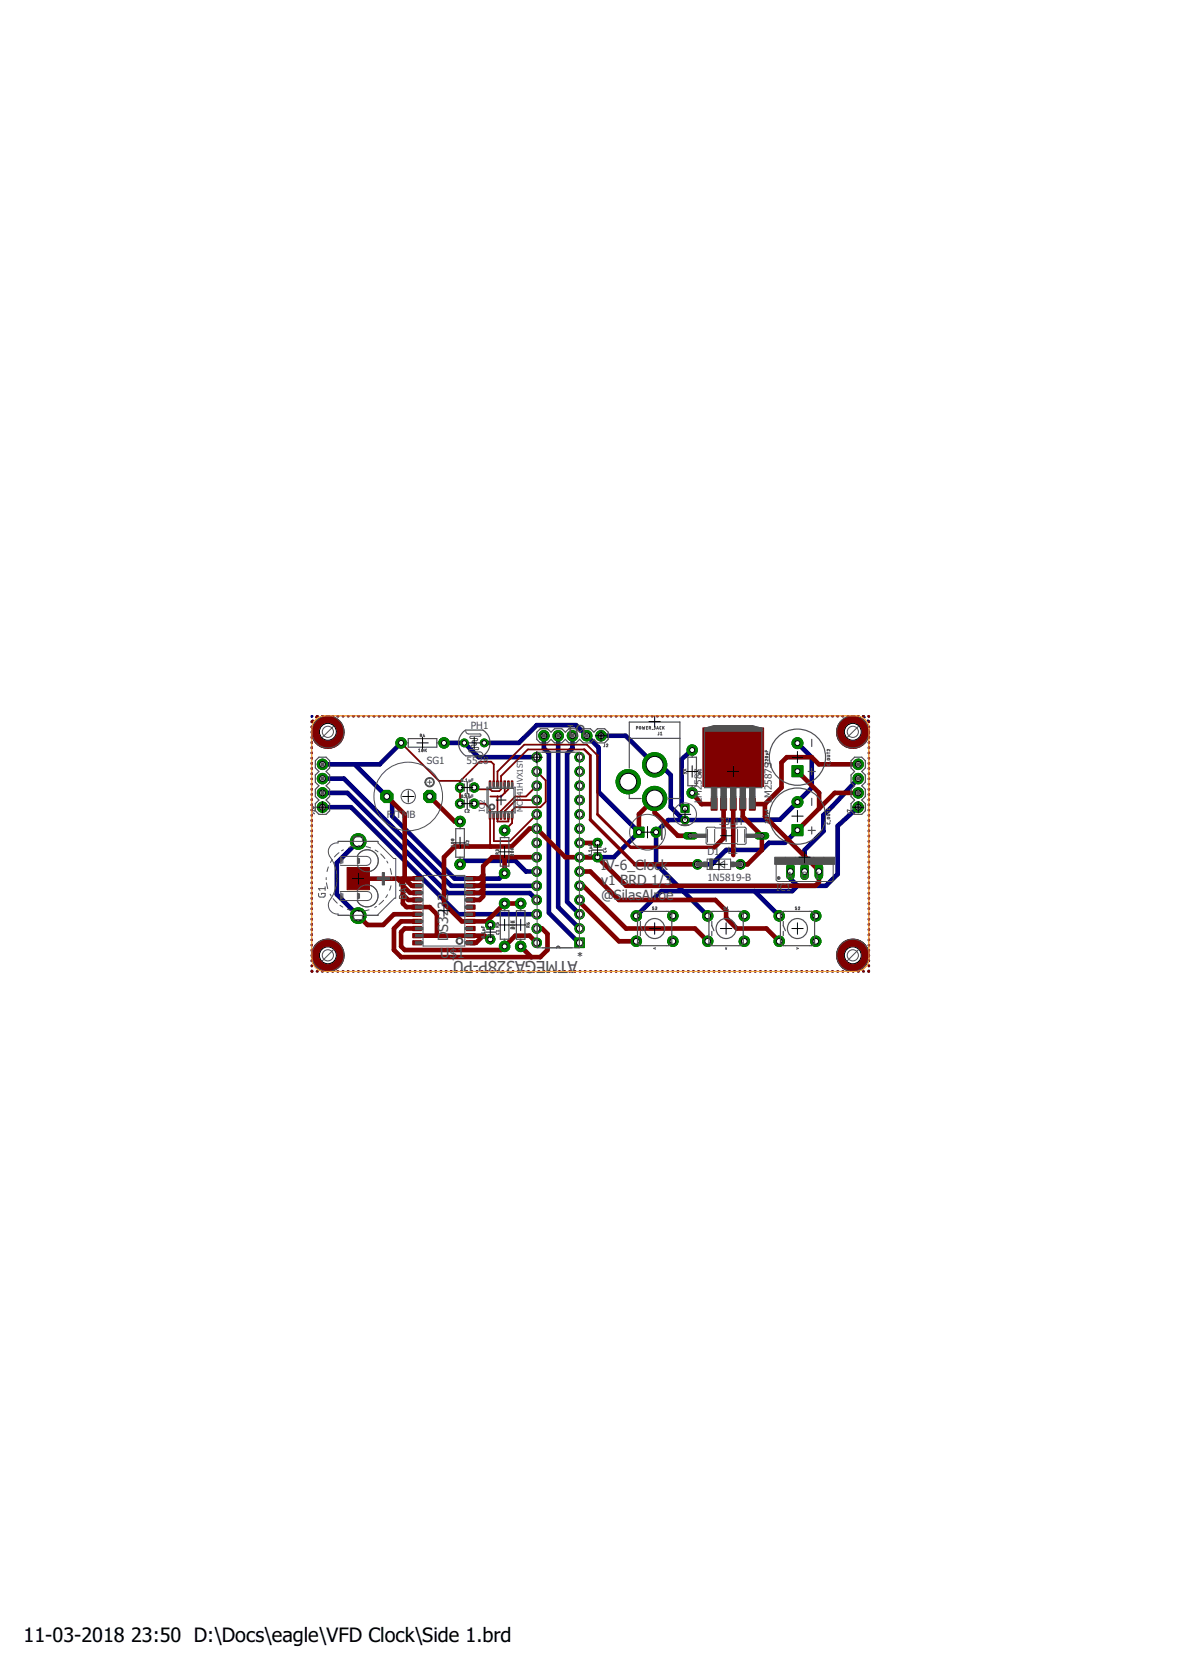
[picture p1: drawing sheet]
<svg xmlns="http://www.w3.org/2000/svg" width="210mm" height="297mm" viewBox="0 0 210 297" stroke-linecap="round" stroke-linejoin="round" font-family="sans-serif">
<defs><g id="words">
<g font-size="3.5">
<text x="4.2" y="291.8">11-03-2018</text>
<text x="23.3" y="291.8">23:50 D:\Docs\eagle\VFD Clock\Side 1.brd</text>
</g>
<g font-size="2.9" fill="#505050">
<text x="104.1" y="128.8" transform="rotate(-180 104.1 128.8)">U1</text>
<text x="102.7" y="170.8" transform="rotate(-180 102.7 170.8)">ATMEGA328P-PU</text>
</g>
<g font-size="2.5" fill="#505050">
<text x="106.8" y="154.7">IV-6_Clock</text>
<text x="79.7" y="161.5" transform="rotate(-90 79.7 161.5)">32</text>
<text x="106.8" y="157.3">v1 BRD 1/3</text>
<text x="106.8" y="160">@SilasAlroe</text>
<text x="79.7" y="167.3" transform="rotate(-90 79.7 167.3)">D</text>
<text x="79.7" y="165.7" transform="rotate(-90 79.7 165.7)">S32</text>
<text x="78.2" y="170.3">U$1</text>
</g>
<g font-size="1.8" fill="#505050">
<text x="83.7" y="129.5">PH1</text>
<text x="75.9" y="135.9">SG1</text>
<text x="82.9" y="135.9">5528</text>
<text x="124.7" y="142.7" transform="rotate(-90 124.7 142.7)">LM2587</text>
<text x="137.2" y="142.7" transform="rotate(-90 137.2 142.7)">LM2587S</text>
<text x="68.7" y="145.4">F/TMB</text>
<text x="127.8" y="146.6">3</text>
<text x="128.8" y="146.6">3µ</text>
<text x="130.8" y="146.6">H</text>
<text x="125.7" y="152">D1</text>
<text x="129.3" y="151.7">L1</text>
<text x="125.7" y="156.6">1N5819-B</text>
<text x="137.9" y="158.4">IC1</text>
<text x="139.8" y="156.2">A</text>
<text x="142.4" y="156.2">O</text>
<text x="144.9" y="156.2">I</text>
<text x="103.6" y="168.7" transform="rotate(-180 103.6 168.7)">*</text>
</g>
<g font-size="1.4" fill="#505050">
<text x="92.9" y="143.2" transform="rotate(-90 92.9 143.2)">CP41HVX1ST</text>
<text x="86.2" y="144.3" transform="rotate(-90 86.2 144.3)">IC2</text>
<text x="92.9" y="144.3" transform="rotate(-90 92.9 144.3)">M</text>
</g>
</g></defs>
<g fill="#000080" stroke="#000080" stroke-width=".18">
<path d="M56 168a2.88 2.88 0 0 1 4.6 .2 2.88 2.88 0 0 1-1.5 4.4 2.88 2.88 0 0 1-3.7-2.8h2.5a.35 .35 0 0 1 .5-.4 .35 .35 0 0 1 .1 .6 .35 .35 0 0 1-.6-.1l-2.5-.1 .1-.6z" fill-rule="evenodd"/>
<path d="M56 128.4a2.89 2.89 0 0 1 4.7 .1 2.89 2.89 0 0 1-1.5 4.4 2.89 2.89 0 0 1-3.8-2.7h2.5a.35 .35 0 0 1 .5-.4 .35 .35 0 0 1 .1 .6 .35 .35 0 0 1-.6-.2h-2.5l.1-.7z" fill-rule="evenodd"/>
<path d="M149.3 128.4a2.88 2.88 0 0 1 4.7 .1 2.88 2.88 0 0 1-1.6 4.4 2.88 2.88 0 0 1-3.7-2.7h2.5a.35 .35 0 0 1 .6-.3 .35 .35 0 0 1 0 .6 .35 .35 0 0 1-.6-.3h-2.5l.3-1.3z" fill-rule="evenodd"/>
<path d="M149.8 167.6a2.89 2.89 0 0 1 4.4 .9 2.89 2.89 0 0 1-2 4.1 2.89 2.89 0 0 1-3.5-2.8h2.5a.35 .35 0 0 1 .6-.2 .35 .35 0 0 1 0 .6 .35 .35 0 0 1-.6-.3l-2.5-.1a2.87 2.87 0 0 1 1.1-2.2z" fill-rule="evenodd"/>
</g>
<g fill="none" stroke="#000080" stroke-width=".83">
<path d="M57.3 138.4h3.8l19.1 19.1h15.2M63 135.9l6.7 6.6v2.6l11.1 11.1h7.9l1-1M71.3 132.1l-3.8 3.8h-10.2M78.9 132.1h3.6l2.5 2.5h10.4M86.1 132.1h6.1l3.2-3.2h7l4 4v7.9l7.2 7.1-4.5 4.5h-6.1M96.7 130.8v2.2l.9 .9v28.4l5.4 5.3M99.2 130.8v30.4l3.8 3.9M101.7 130.8v2.2l-.9 1v26.3l2.2 2.2M106.8 130.8h4.4l5.2 5.2h1l1.8 1.8v5.7l2.3 2.3M123 133.3l-1.9 1.7v8.1l.7 .6M141.7 132.1l2.6 2.5v5.4l-5.7 5.7-19.8 .1-2.2 2.1v5.7l9.2 9.2M152.5 138.4l-6.2 6.5v2.9l-3.3 3.3v3.8"/>
<path d="M57.3 140.9h4.5l17.8 17.8h14.6l1.2 1.3M57.3 143.5h5.1l19 19h14M63.7 149.6l-3.8 3.8v5.6l3.8 3.8M81.8 153.6l.6-.6h9.2l1.9 1.9h1.9M134.1 158.4l4.4 4.4M140.5 154.9v1.3l1.2 1.3M141.7 142.2v.4M141.7 157.5l-.9 .9h-23.3l-4.4 4.4M141.7 147.6l-2.2 2.2h-2.8l-1.3 1.3h-6.3l-2.6 2.5h-2.5M152.5 143.5l-3.6 3.3v8.6l-2.1 2.1h-5.1"/>
</g>
<g fill="none" stroke="#000080" stroke-width=".42">
<path d="M55.4 128.2v.1M55.4 129.2v.1M55.4 130.1v.1M55.4 131v.1M55.4 131.9v.1M55.4 132.8v.2M55.4 133.8v.1M55.4 134.7v.1M55.4 135.6v.1M55.4 136.5v.2M55.4 137.5v.1M55.4 138.4v.1"/>
<path d="M55.4 139.3v.1M55.5 127.3l-.1 .1M56.3 127.3h.1M57.3 127.3h.1M58.2 127.3h.1M59.1 127.3h.1M60 127.3h.1M60.9 127.3h.1M61.8 127.3h.1M62.7 127.3h.1M63.6 127.3h.2M64.6 127.3h.1"/>
<path d="M65.5 127.3h.1M66.4 127.3h.1M67.3 127.3h.1M68.2 127.3h.1M69.2 127.3h.1M70.1 127.3h.1M71 127.3h.1M71.9 127.3h.1M72.8 127.3h.1M73.7 127.3h.1M74.6 127.3h.1M75.6 127.3h.1"/>
<path d="M76.5 127.3h.1M77.4 127.3h.1M78.3 127.3h.1M79.2 127.3h.1M80.1 127.3h.1M81 127.3h.2M82 127.3h.1M82.9 127.3h.1M83.8 127.3h.1M84.7 127.3h.1M85.6 127.3h.1M86.6 127.3h.1"/>
<path d="M87.5 127.3h.1M88.4 127.3h.1M89.3 127.3h.1M90.2 127.3h.1M91.1 127.3h.1M92 127.3h.1M93 127.3h.1M93.9 127.3h.1M94.8 127.3h.1M95.7 127.3h.1M96.6 127.3h.1M97.5 127.3h.1"/>
<path d="M98.4 127.3h.2M99.4 127.3h.1M100.3 127.3h.1M101.2 127.3h.1M102.1 127.3h.1M103 127.3h.1M103.9 127.3h.1M104.9 127.3h.1M105.8 127.3h.1M106.7 127.3h.1M107.6 127.3h.1M108.5 127.3h.1"/>
<path d="M109.4 127.3h.1M110.3 127.3h.1M111.3 127.3h.1M112.2 127.3h.1M113.1 127.3h.1M114 127.3h.1M114.9 127.3h.1M115.8 127.3h.2M116.8 127.3h.1M117.7 127.3h.1M118.6 127.3h.1M119.5 127.3h.1"/>
<path d="M120.4 127.3h.1M121.3 127.3h.1M122.3 127.3h.1M123.2 127.3h.1M124.1 127.3h.1M125 127.3h.1M125.9 127.3h.1M126.8 127.3h.1M127.7 127.3h.1M128.7 127.3h.1M129.6 127.3h.1M130.5 127.3h.1"/>
<path d="M131.4 127.3h.1M132.3 127.3h.1M133.2 127.3h.1M134.2 127.3h.1M135.1 127.3h.1M136 127.3h.1M136.9 127.3h.1M137.8 127.3h.1M138.7 127.3h.1M139.7 127.3h.1M140.6 127.3h.1M141.5 127.3h.1"/>
<path d="M142.4 127.3h.1M143.3 127.3h.1M144.2 127.3h.1M145.1 127.3h.1M146 127.3h.2M147 127.3h.1M147.9 127.3h.1M148.8 127.3h.1M149.7 127.3h.1M150.6 127.3h.1M151.6 127.3h.1M152.5 127.3h.1"/>
<path d="M153.4 127.3l.3 .2M154.2 128.1l.2 .3M154.4 129.2v.1M154.4 130.1v.1M154.4 131v.1M154.4 132v.1M154.4 132.9v.1M154.4 133.8v.1M154.4 134.7v.1M154.4 135.6v.2M154.4 136.6v.1M154.4 137.5v.1"/>
<path d="M154.4 138.4v.1M154.4 139.3v.1M55.4 140.2v.2M55.4 141.2v.1M55.4 142.1v.1M55.4 143v.1M55.4 143.9v.1M55.4 144.9v.1M55.4 145.8v.1M55.4 146.7v.1M55.4 147.6v.1M55.4 148.5v.2"/>
<path d="M55.4 149.5v.1M55.4 150.4v.1M55.4 151.3v.1M55.4 152.3v.1M55.4 153.2v.1M55.4 154.1v.1M55.4 155v.1M55.4 155.9v.2M55.4 156.9v.1M55.4 157.8v.1M55.4 158.7v.1M55.4 159.6v.1"/>
<path d="M154.4 140.3v.1M154.4 141.2v.1M154.4 142.1v.1M154.4 143v.2M154.4 144v.1M154.4 144.9v.1M154.4 145.8v.1M154.4 146.7v.1M154.4 147.6v.2M154.4 148.6v.1M154.4 149.5v.1M154.4 150.4v.1"/>
<path d="M154.4 151.3v.1M154.4 152.3v.1M154.4 153.2v.1M154.4 154.1v.1M154.4 155v.1M154.4 156v.1M154.4 156.9v.1M154.4 157.8v.1M154.4 158.7v.1M154.4 159.6v.1M55.4 160.5v.2M55.4 161.5v.1"/>
<path d="M55.4 162.4v.1M55.4 163.3v.1M55.4 164.3v.1M55.4 165.2v.1M55.4 166.1v.1M55.4 167v.1M55.4 168v.1M55.4 168.9v.1M55.4 169.8v.1M55.4 170.7v.1M55.4 171.6v.1M55.4 172.6l.1 .1"/>
<path d="M56.3 172.7h.1M57.3 172.7h.1M58.2 172.7h.1M59.1 172.7h.1M60 172.7h.1M60.9 172.7h.1M61.8 172.7h.1M62.7 172.7h.1M63.6 172.7h.2M64.6 172.7h.1M65.5 172.7h.1M66.4 172.7h.1"/>
<path d="M67.3 172.7h.1M68.2 172.7h.1M69.2 172.7h.1M70.1 172.7h.1M71 172.7h.1M71.9 172.7h.1M72.8 172.7h.1M73.7 172.7h.1M74.7 172.7h.1M75.6 172.7h.1M76.5 172.7h.1M77.4 172.7h.1"/>
<path d="M78.3 172.7h.1M79.2 172.7h.1M80.1 172.7h.1M81.1 172.7h.1M82 172.7h.1M82.9 172.7h.1M83.8 172.7h.1M84.7 172.7h.1M85.6 172.7h.1M86.6 172.7h.1M87.5 172.7h.1M88.4 172.7h.1"/>
<path d="M89.3 172.7h.1M90.2 172.7h.1M91.1 172.7h.1M92.1 172.7h.1M93 172.7h.1M93.9 172.7h.1M94.8 172.7h.1M95.7 172.7h.1M96.6 172.7h.1M97.6 172.7h.1M98.5 172.7h.1M99.4 172.7h.1"/>
<path d="M100.3 172.7h.1M101.2 172.7h.1M102.1 172.7h.1M103 172.7h.1M103.9 172.7h.2M104.9 172.7h.1M105.8 172.7h.1M106.7 172.7h.1M107.6 172.7h.1M108.5 172.7h.1M109.5 172.7h.1M110.4 172.7h.1"/>
<path d="M111.3 172.7h.1M112.2 172.7h.1M113.1 172.7h.1M114 172.7h.1M115 172.7h.1M115.9 172.7h.1M116.8 172.7h.1M117.7 172.7h.1M118.6 172.7h.1M119.5 172.7h.1M120.4 172.7h.1M121.4 172.7h.1"/>
<path d="M122.3 172.7h.1M123.2 172.7h.1M124.1 172.7h.1M125 172.7h.1M125.9 172.7h.1M126.9 172.7h.1M127.8 172.7h.1M128.7 172.7h.1M129.6 172.7h.1M130.5 172.7h.1M131.4 172.7h.1M132.4 172.7h.1"/>
<path d="M133.3 172.7h.1M134.2 172.7h.1M135.1 172.7h.1M136 172.7h.1M136.9 172.7h.1M137.8 172.7h.1M138.8 172.7h.1M139.7 172.7h.1M140.6 172.7h.1M141.5 172.7h.1M142.4 172.7h.1M143.3 172.7h.1"/>
<path d="M144.3 172.7h.1M145.2 172.7h.1M146.1 172.7h.1M147 172.7h.1M147.9 172.7h.1M148.8 172.7h.1M149.8 172.7h.1M150.7 172.7h.1M151.6 172.7h.1M152.5 172.7h.1M153.4 172.7h.1M154.4 160.6v.1"/>
<path d="M154.4 161.5v.1M154.4 162.4v.1M154.4 163.3v.1M154.4 164.3v.1M154.4 165.2v.1M154.4 166.1v.1M154.4 167v.1M154.4 168v.1M154.4 168.9v.1M154.4 169.8v.1M154.4 170.7v.1M154.4 171.6v.1"/>
<path d="M154.4 172.6l-.1 .1"/>
</g>
<circle cx="121.8" cy="145.8" r=".7" fill="#008000" stroke="#008000" stroke-width=".18"/>
<circle cx="121.8" cy="145.8" r=".44" fill="#fff" stroke="#000" stroke-width=".18"/>
<path d="M121.1 143h1.3v1.4h-1.3z" fill="#008000" stroke="#008000" stroke-width=".18"/>
<circle cx="121.8" cy="143.7" r=".44" fill="#fff" stroke="#000" stroke-width=".18"/>
<path d="M112.7 147h1.7v1.8h-1.7z" fill="#008000" stroke="#008000" stroke-width=".18"/>
<circle cx="113.6" cy="147.9" r=".44" fill="#fff" stroke="#000" stroke-width=".18"/>
<circle cx="116.6" cy="147.9" r=".89" fill="#008000" stroke="#008000" stroke-width=".18"/>
<circle cx="116.6" cy="147.9" r=".44" fill="#fff" stroke="#000" stroke-width=".18"/>
<circle cx="141.7" cy="142.6" r=".97" fill="#008000" stroke="#008000" stroke-width=".18"/>
<circle cx="141.7" cy="142.6" r=".44" fill="#fff" stroke="#000" stroke-width=".18"/>
<path d="M140.8 146.6h1.9v1.9h-1.9z" fill="#008000" stroke="#008000" stroke-width=".18"/>
<circle cx="141.7" cy="147.6" r=".44" fill="#fff" stroke="#000" stroke-width=".18"/>
<circle cx="141.7" cy="132.1" r=".97" fill="#008000" stroke="#008000" stroke-width=".18"/>
<circle cx="141.7" cy="132.1" r=".44" fill="#fff" stroke="#000" stroke-width=".18"/>
<path d="M140.8 136.1h1.9v2h-1.9z" fill="#008000" stroke="#008000" stroke-width=".18"/>
<circle cx="141.7" cy="137.1" r=".44" fill="#fff" stroke="#000" stroke-width=".18"/>
<circle cx="124" cy="153.6" r=".85" fill="#008000" stroke="#008000" stroke-width=".18"/>
<circle cx="124" cy="153.6" r=".55" fill="#fff" stroke="#000" stroke-width=".18"/>
<circle cx="131.6" cy="153.6" r=".85" fill="#008000" stroke="#008000" stroke-width=".18"/>
<circle cx="131.6" cy="153.6" r=".55" fill="#fff" stroke="#000" stroke-width=".18"/>
<path d="M134.7 148.6h1.4" fill="none" stroke="#008000" stroke-width="1.3"/>
<circle cx="135.4" cy="148.6" r=".4" fill="#fff" stroke="#000" stroke-width=".18"/>
<path d="M122 148.6h1.4" fill="none" stroke="#008000" stroke-width="1.3"/>
<circle cx="122.7" cy="148.6" r=".4" fill="#fff" stroke="#000" stroke-width=".18"/>
<circle cx="123" cy="133.3" r=".93" fill="#008000" stroke="#008000" stroke-width=".18"/>
<circle cx="123" cy="133.3" r=".44" fill="#fff" stroke="#000" stroke-width=".18"/>
<circle cx="123" cy="140.9" r=".93" fill="#008000" stroke="#008000" stroke-width=".18"/>
<circle cx="123" cy="140.9" r=".44" fill="#fff" stroke="#000" stroke-width=".18"/>
<circle cx="116.4" cy="141.9" r="2.16" fill="#008000" stroke="#008000" stroke-width=".18"/>
<circle cx="116.4" cy="141.9" r="1.5" fill="#fff" stroke="#000" stroke-width=".18"/>
<circle cx="116.4" cy="136" r="2.16" fill="#008000" stroke="#008000" stroke-width=".18"/>
<circle cx="116.4" cy="136" r="1.5" fill="#fff" stroke="#000" stroke-width=".18"/>
<circle cx="111.7" cy="139" r="2.16" fill="#008000" stroke="#008000" stroke-width=".18"/>
<circle cx="111.7" cy="139" r="1.5" fill="#fff" stroke="#000" stroke-width=".18"/>
<circle cx="152.5" cy="143.5" r=".93" fill="#008000" stroke="#008000" stroke-width=".18"/>
<circle cx="152.5" cy="143.5" r=".51" fill="#fff" stroke="#000" stroke-width=".18"/>
<circle cx="152.5" cy="140.9" r=".93" fill="#008000" stroke="#008000" stroke-width=".18"/>
<circle cx="152.5" cy="140.9" r=".51" fill="#fff" stroke="#000" stroke-width=".18"/>
<circle cx="152.5" cy="138.4" r=".93" fill="#008000" stroke="#008000" stroke-width=".18"/>
<circle cx="152.5" cy="138.4" r=".51" fill="#fff" stroke="#000" stroke-width=".18"/>
<circle cx="152.5" cy="135.9" r=".93" fill="#008000" stroke="#008000" stroke-width=".18"/>
<circle cx="152.5" cy="135.9" r=".51" fill="#fff" stroke="#000" stroke-width=".18"/>
<circle cx="57.3" cy="143.5" r=".93" fill="#008000" stroke="#008000" stroke-width=".18"/>
<circle cx="57.3" cy="143.5" r=".51" fill="#fff" stroke="#000" stroke-width=".18"/>
<circle cx="57.3" cy="140.9" r=".93" fill="#008000" stroke="#008000" stroke-width=".18"/>
<circle cx="57.3" cy="140.9" r=".51" fill="#fff" stroke="#000" stroke-width=".18"/>
<circle cx="57.3" cy="138.4" r=".93" fill="#008000" stroke="#008000" stroke-width=".18"/>
<circle cx="57.3" cy="138.4" r=".51" fill="#fff" stroke="#000" stroke-width=".18"/>
<circle cx="57.3" cy="135.9" r=".93" fill="#008000" stroke="#008000" stroke-width=".18"/>
<circle cx="57.3" cy="135.9" r=".51" fill="#fff" stroke="#000" stroke-width=".18"/>
<circle cx="86.1" cy="132.1" r=".7" fill="#008000" stroke="#008000" stroke-width=".18"/>
<circle cx="86.1" cy="132.1" r=".4" fill="#fff" stroke="#000" stroke-width=".18"/>
<circle cx="82.5" cy="132.1" r=".7" fill="#008000" stroke="#008000" stroke-width=".18"/>
<circle cx="82.5" cy="132.1" r=".4" fill="#fff" stroke="#000" stroke-width=".18"/>
<circle cx="71.3" cy="132.1" r=".93" fill="#008000" stroke="#008000" stroke-width=".18"/>
<circle cx="71.3" cy="132.1" r=".44" fill="#fff" stroke="#000" stroke-width=".18"/>
<circle cx="78.9" cy="132.1" r=".93" fill="#008000" stroke="#008000" stroke-width=".18"/>
<circle cx="78.9" cy="132.1" r=".44" fill="#fff" stroke="#000" stroke-width=".18"/>
<circle cx="125.8" cy="162.8" r=".93" fill="#008000" stroke="#008000" stroke-width=".18"/>
<circle cx="125.8" cy="162.8" r=".51" fill="#fff" stroke="#000" stroke-width=".18"/>
<circle cx="132.3" cy="162.8" r=".93" fill="#008000" stroke="#008000" stroke-width=".18"/>
<circle cx="132.3" cy="162.8" r=".51" fill="#fff" stroke="#000" stroke-width=".18"/>
<circle cx="125.8" cy="167.3" r=".93" fill="#008000" stroke="#008000" stroke-width=".18"/>
<circle cx="125.8" cy="167.3" r=".51" fill="#fff" stroke="#000" stroke-width=".18"/>
<circle cx="132.3" cy="167.3" r=".93" fill="#008000" stroke="#008000" stroke-width=".18"/>
<circle cx="132.3" cy="167.3" r=".51" fill="#fff" stroke="#000" stroke-width=".18"/>
<path d="M140.5 154.2v1.5" fill="none" stroke="#008000" stroke-width="1.5"/>
<circle cx="140.5" cy="154.9" r=".51" fill="#fff" stroke="#000" stroke-width=".18"/>
<path d="M143 154.2v1.5" fill="none" stroke="#008000" stroke-width="1.5"/>
<circle cx="143" cy="154.9" r=".51" fill="#fff" stroke="#000" stroke-width=".18"/>
<path d="M145.5 154.2v1.5" fill="none" stroke="#008000" stroke-width="1.5"/>
<circle cx="145.5" cy="154.9" r=".51" fill="#fff" stroke="#000" stroke-width=".18"/>
<circle cx="138.5" cy="162.8" r=".93" fill="#008000" stroke="#008000" stroke-width=".18"/>
<circle cx="138.5" cy="162.8" r=".51" fill="#fff" stroke="#000" stroke-width=".18"/>
<circle cx="145" cy="162.8" r=".93" fill="#008000" stroke="#008000" stroke-width=".18"/>
<circle cx="145" cy="162.8" r=".51" fill="#fff" stroke="#000" stroke-width=".18"/>
<circle cx="138.5" cy="167.3" r=".93" fill="#008000" stroke="#008000" stroke-width=".18"/>
<circle cx="138.5" cy="167.3" r=".51" fill="#fff" stroke="#000" stroke-width=".18"/>
<circle cx="145" cy="167.3" r=".93" fill="#008000" stroke="#008000" stroke-width=".18"/>
<circle cx="145" cy="167.3" r=".51" fill="#fff" stroke="#000" stroke-width=".18"/>
<circle cx="113.1" cy="162.8" r=".93" fill="#008000" stroke="#008000" stroke-width=".18"/>
<circle cx="113.1" cy="162.8" r=".51" fill="#fff" stroke="#000" stroke-width=".18"/>
<circle cx="119.6" cy="162.8" r=".93" fill="#008000" stroke="#008000" stroke-width=".18"/>
<circle cx="119.6" cy="162.8" r=".51" fill="#fff" stroke="#000" stroke-width=".18"/>
<circle cx="113.1" cy="167.3" r=".93" fill="#008000" stroke="#008000" stroke-width=".18"/>
<circle cx="113.1" cy="167.3" r=".51" fill="#fff" stroke="#000" stroke-width=".18"/>
<circle cx="119.6" cy="167.3" r=".93" fill="#008000" stroke="#008000" stroke-width=".18"/>
<circle cx="119.6" cy="167.3" r=".51" fill="#fff" stroke="#000" stroke-width=".18"/>
<circle cx="68.7" cy="141.6" r="1.17" fill="#008000" stroke="#008000" stroke-width=".18"/>
<circle cx="68.7" cy="141.6" r=".51" fill="#fff" stroke="#000" stroke-width=".18"/>
<circle cx="76.4" cy="141.6" r="1.17" fill="#008000" stroke="#008000" stroke-width=".18"/>
<circle cx="76.4" cy="141.6" r=".51" fill="#fff" stroke="#000" stroke-width=".18"/>
<circle cx="81.8" cy="146" r=".93" fill="#008000" stroke="#008000" stroke-width=".18"/>
<circle cx="81.8" cy="146" r=".44" fill="#fff" stroke="#000" stroke-width=".18"/>
<circle cx="81.8" cy="153.6" r=".93" fill="#008000" stroke="#008000" stroke-width=".18"/>
<circle cx="81.8" cy="153.6" r=".44" fill="#fff" stroke="#000" stroke-width=".18"/>
<path d="M102.2 166.8h1.7v1.6h-1.7z" fill="#008000" stroke="#008000" stroke-width=".18"/>
<circle cx="103" cy="167.6" r=".55" fill="#fff" stroke="#000" stroke-width=".18"/>
<circle cx="103" cy="165.1" r=".85" fill="#008000" stroke="#008000" stroke-width=".18"/>
<circle cx="103" cy="165.1" r=".55" fill="#fff" stroke="#000" stroke-width=".18"/>
<circle cx="103" cy="162.5" r=".85" fill="#008000" stroke="#008000" stroke-width=".18"/>
<circle cx="103" cy="162.5" r=".55" fill="#fff" stroke="#000" stroke-width=".18"/>
<circle cx="103" cy="160" r=".85" fill="#008000" stroke="#008000" stroke-width=".18"/>
<circle cx="103" cy="160" r=".55" fill="#fff" stroke="#000" stroke-width=".18"/>
<circle cx="103" cy="157.5" r=".85" fill="#008000" stroke="#008000" stroke-width=".18"/>
<circle cx="103" cy="157.5" r=".55" fill="#fff" stroke="#000" stroke-width=".18"/>
<circle cx="103" cy="154.9" r=".85" fill="#008000" stroke="#008000" stroke-width=".18"/>
<circle cx="103" cy="154.9" r=".55" fill="#fff" stroke="#000" stroke-width=".18"/>
<circle cx="103" cy="152.4" r=".85" fill="#008000" stroke="#008000" stroke-width=".18"/>
<circle cx="103" cy="152.4" r=".55" fill="#fff" stroke="#000" stroke-width=".18"/>
<circle cx="103" cy="149.8" r=".85" fill="#008000" stroke="#008000" stroke-width=".18"/>
<circle cx="103" cy="149.8" r=".55" fill="#fff" stroke="#000" stroke-width=".18"/>
<circle cx="103" cy="147.3" r=".85" fill="#008000" stroke="#008000" stroke-width=".18"/>
<circle cx="103" cy="147.3" r=".55" fill="#fff" stroke="#000" stroke-width=".18"/>
<circle cx="103" cy="144.8" r=".85" fill="#008000" stroke="#008000" stroke-width=".18"/>
<circle cx="103" cy="144.8" r=".55" fill="#fff" stroke="#000" stroke-width=".18"/>
<circle cx="103" cy="142.2" r=".85" fill="#008000" stroke="#008000" stroke-width=".18"/>
<circle cx="103" cy="142.2" r=".55" fill="#fff" stroke="#000" stroke-width=".18"/>
<circle cx="103" cy="139.7" r=".85" fill="#008000" stroke="#008000" stroke-width=".18"/>
<circle cx="103" cy="139.7" r=".55" fill="#fff" stroke="#000" stroke-width=".18"/>
<circle cx="103" cy="137.1" r=".85" fill="#008000" stroke="#008000" stroke-width=".18"/>
<circle cx="103" cy="137.1" r=".55" fill="#fff" stroke="#000" stroke-width=".18"/>
<circle cx="103" cy="134.6" r=".85" fill="#008000" stroke="#008000" stroke-width=".18"/>
<circle cx="103" cy="134.6" r=".55" fill="#fff" stroke="#000" stroke-width=".18"/>
<circle cx="95.4" cy="134.6" r=".85" fill="#008000" stroke="#008000" stroke-width=".18"/>
<circle cx="95.4" cy="134.6" r=".55" fill="#fff" stroke="#000" stroke-width=".18"/>
<circle cx="95.4" cy="137.1" r=".85" fill="#008000" stroke="#008000" stroke-width=".18"/>
<circle cx="95.4" cy="137.1" r=".55" fill="#fff" stroke="#000" stroke-width=".18"/>
<circle cx="95.4" cy="139.7" r=".85" fill="#008000" stroke="#008000" stroke-width=".18"/>
<circle cx="95.4" cy="139.7" r=".55" fill="#fff" stroke="#000" stroke-width=".18"/>
<circle cx="95.4" cy="142.2" r=".85" fill="#008000" stroke="#008000" stroke-width=".18"/>
<circle cx="95.4" cy="142.2" r=".55" fill="#fff" stroke="#000" stroke-width=".18"/>
<circle cx="95.4" cy="144.8" r=".85" fill="#008000" stroke="#008000" stroke-width=".18"/>
<circle cx="95.4" cy="144.8" r=".55" fill="#fff" stroke="#000" stroke-width=".18"/>
<circle cx="95.4" cy="147.3" r=".85" fill="#008000" stroke="#008000" stroke-width=".18"/>
<circle cx="95.4" cy="147.3" r=".55" fill="#fff" stroke="#000" stroke-width=".18"/>
<circle cx="95.4" cy="149.8" r=".85" fill="#008000" stroke="#008000" stroke-width=".18"/>
<circle cx="95.4" cy="149.8" r=".55" fill="#fff" stroke="#000" stroke-width=".18"/>
<circle cx="95.4" cy="152.4" r=".85" fill="#008000" stroke="#008000" stroke-width=".18"/>
<circle cx="95.4" cy="152.4" r=".55" fill="#fff" stroke="#000" stroke-width=".18"/>
<circle cx="95.4" cy="154.9" r=".85" fill="#008000" stroke="#008000" stroke-width=".18"/>
<circle cx="95.4" cy="154.9" r=".55" fill="#fff" stroke="#000" stroke-width=".18"/>
<circle cx="95.4" cy="157.5" r=".85" fill="#008000" stroke="#008000" stroke-width=".18"/>
<circle cx="95.4" cy="157.5" r=".55" fill="#fff" stroke="#000" stroke-width=".18"/>
<circle cx="95.4" cy="160" r=".85" fill="#008000" stroke="#008000" stroke-width=".18"/>
<circle cx="95.4" cy="160" r=".55" fill="#fff" stroke="#000" stroke-width=".18"/>
<circle cx="95.4" cy="162.5" r=".85" fill="#008000" stroke="#008000" stroke-width=".18"/>
<circle cx="95.4" cy="162.5" r=".55" fill="#fff" stroke="#000" stroke-width=".18"/>
<circle cx="95.4" cy="165.1" r=".85" fill="#008000" stroke="#008000" stroke-width=".18"/>
<circle cx="95.4" cy="165.1" r=".55" fill="#fff" stroke="#000" stroke-width=".18"/>
<circle cx="95.4" cy="167.6" r=".85" fill="#008000" stroke="#008000" stroke-width=".18"/>
<circle cx="95.4" cy="167.6" r=".55" fill="#fff" stroke="#000" stroke-width=".18"/>
<circle cx="63.7" cy="162.8" r="1.4" fill="#008000" stroke="#008000" stroke-width=".18"/>
<circle cx="63.7" cy="162.8" r=".93" fill="#fff" stroke="#000" stroke-width=".18"/>
<circle cx="63.7" cy="149.6" r="1.4" fill="#008000" stroke="#008000" stroke-width=".18"/>
<circle cx="63.7" cy="149.6" r=".93" fill="#fff" stroke="#000" stroke-width=".18"/>
<circle cx="106.8" cy="130.8" r=".93" fill="#008000" stroke="#008000" stroke-width=".18"/>
<circle cx="106.8" cy="130.8" r=".51" fill="#fff" stroke="#000" stroke-width=".18"/>
<circle cx="104.3" cy="130.8" r=".93" fill="#008000" stroke="#008000" stroke-width=".18"/>
<circle cx="104.3" cy="130.8" r=".51" fill="#fff" stroke="#000" stroke-width=".18"/>
<circle cx="101.7" cy="130.8" r=".93" fill="#008000" stroke="#008000" stroke-width=".18"/>
<circle cx="101.7" cy="130.8" r=".51" fill="#fff" stroke="#000" stroke-width=".18"/>
<circle cx="99.2" cy="130.8" r=".93" fill="#008000" stroke="#008000" stroke-width=".18"/>
<circle cx="99.2" cy="130.8" r=".51" fill="#fff" stroke="#000" stroke-width=".18"/>
<circle cx="96.7" cy="130.8" r=".93" fill="#008000" stroke="#008000" stroke-width=".18"/>
<circle cx="96.7" cy="130.8" r=".51" fill="#fff" stroke="#000" stroke-width=".18"/>
<circle cx="89.7" cy="155.2" r=".93" fill="#008000" stroke="#008000" stroke-width=".18"/>
<circle cx="89.7" cy="155.2" r=".44" fill="#fff" stroke="#000" stroke-width=".18"/>
<circle cx="89.7" cy="147.6" r=".93" fill="#008000" stroke="#008000" stroke-width=".18"/>
<circle cx="89.7" cy="147.6" r=".44" fill="#fff" stroke="#000" stroke-width=".18"/>
<circle cx="89.7" cy="168.2" r=".93" fill="#008000" stroke="#008000" stroke-width=".18"/>
<circle cx="89.7" cy="168.2" r=".44" fill="#fff" stroke="#000" stroke-width=".18"/>
<circle cx="89.7" cy="160.6" r=".93" fill="#008000" stroke="#008000" stroke-width=".18"/>
<circle cx="89.7" cy="160.6" r=".44" fill="#fff" stroke="#000" stroke-width=".18"/>
<circle cx="92.5" cy="160.6" r=".93" fill="#008000" stroke="#008000" stroke-width=".18"/>
<circle cx="92.5" cy="160.6" r=".44" fill="#fff" stroke="#000" stroke-width=".18"/>
<circle cx="92.5" cy="168.2" r=".93" fill="#008000" stroke="#008000" stroke-width=".18"/>
<circle cx="92.5" cy="168.2" r=".44" fill="#fff" stroke="#000" stroke-width=".18"/>
<circle cx="87.1" cy="164.4" r=".83" fill="#008000" stroke="#008000" stroke-width=".18"/>
<circle cx="87.1" cy="164.4" r=".44" fill="#fff" stroke="#000" stroke-width=".18"/>
<circle cx="87.1" cy="167" r=".83" fill="#008000" stroke="#008000" stroke-width=".18"/>
<circle cx="87.1" cy="167" r=".44" fill="#fff" stroke="#000" stroke-width=".18"/>
<circle cx="84.3" cy="142.9" r=".83" fill="#008000" stroke="#008000" stroke-width=".18"/>
<circle cx="84.3" cy="142.9" r=".44" fill="#fff" stroke="#000" stroke-width=".18"/>
<circle cx="81.8" cy="142.9" r=".83" fill="#008000" stroke="#008000" stroke-width=".18"/>
<circle cx="81.8" cy="142.9" r=".44" fill="#fff" stroke="#000" stroke-width=".18"/>
<circle cx="84.3" cy="140" r=".83" fill="#008000" stroke="#008000" stroke-width=".18"/>
<circle cx="84.3" cy="140" r=".44" fill="#fff" stroke="#000" stroke-width=".18"/>
<circle cx="81.8" cy="140" r=".83" fill="#008000" stroke="#008000" stroke-width=".18"/>
<circle cx="81.8" cy="140" r=".44" fill="#fff" stroke="#000" stroke-width=".18"/>
<circle cx="106.2" cy="149.8" r=".83" fill="#008000" stroke="#008000" stroke-width=".18"/>
<circle cx="106.2" cy="149.8" r=".44" fill="#fff" stroke="#000" stroke-width=".18"/>
<circle cx="106.2" cy="152.4" r=".83" fill="#008000" stroke="#008000" stroke-width=".18"/>
<circle cx="106.2" cy="152.4" r=".44" fill="#fff" stroke="#000" stroke-width=".18"/>
<g fill="#800000" stroke="#800000" stroke-width=".18">
<path d="M124.9 129.4h10.8v10.4h-10.8z"/>
<path d="M126.4 141.9h1v2.1h-1z"/>
<path d="M128.1 141.9h1v2.1h-1z"/>
<path d="M129.8 141.9h1.1v2.1h-1.1z"/>
<path d="M131.5 141.9h1v2.1h-1z"/>
<path d="M133.2 141.9h1v2.1h-1z"/>
<path d="M82.9 167.2h1.5v.8h-1.5z"/>
<path d="M82.9 165.9h1.5v.8h-1.5z"/>
<path d="M82.9 164.7h1.5v.7h-1.5z"/>
<path d="M82.9 163.4h1.5v.8h-1.5z"/>
<path d="M82.9 162.1h1.5v.8h-1.5z"/>
<path d="M82.9 160.9h1.5v.7h-1.5z"/>
<path d="M82.9 159.6h1.5v.8h-1.5z"/>
<path d="M82.9 158.3h1.5v.8h-1.5z"/>
<path d="M82.9 157.1h1.5v.7h-1.5z"/>
<path d="M82.9 155.8h1.5v.8h-1.5z"/>
<path d="M73.4 157.1h1.5v.7h-1.5z"/>
<path d="M73.4 155.8h1.5v.8h-1.5z"/>
<path d="M73.4 158.3h1.5v.8h-1.5z"/>
<path d="M73.4 159.6h1.5v.8h-1.5z"/>
<path d="M73.4 160.9h1.5v.7h-1.5z"/>
<path d="M73.4 162.1h1.5v.8h-1.5z"/>
<path d="M73.4 163.4h1.5v.8h-1.5z"/>
<path d="M73.4 164.7h1.5v.7h-1.5z"/>
<path d="M73.4 165.9h1.5v.8h-1.5z"/>
<path d="M73.4 167.2h1.5v.8h-1.5z"/>
<path d="M61.7 154.2h4v4h-4z"/>
<path d="M87 144.7h.2v.9h-.2z"/>
<path d="M87.6 144.7h.3v.9h-.3z"/>
<path d="M88.3 144.7h.3v.9h-.3z"/>
<path d="M88.9 144.7h.3v.9h-.3z"/>
<path d="M89.6 144.7h.3v.9h-.3z"/>
<path d="M90.2 144.7h.3v.9h-.3z"/>
<path d="M90.9 144.7h.3v.9h-.3z"/>
<path d="M90.9 138.8h.3v1h-.3z"/>
<path d="M90.2 138.8h.3v1h-.3z"/>
<path d="M89.6 138.8h.3v1h-.3z"/>
<path d="M88.9 138.8h.3v1h-.3z"/>
<path d="M88.3 138.8h.3v1h-.3z"/>
<path d="M87.6 138.8h.3v1h-.3z"/>
<path d="M87 138.8h.2v1h-.2z"/>
</g>
<g fill="none" stroke="#800000" stroke-width=".42">
<path d="M55.4 129.2v.1M55.4 130.1v.1M55.4 131v.1M55.4 132v.1M55.4 132.9v.1M55.4 133.8v.1M55.4 134.7v.1M55.4 135.6v.2M55.4 136.6v.1M55.4 137.5v.1M55.4 138.4v.1M55.4 139.3v.1"/>
<path d="M55.6 128.1l-.2 .3M56.5 127.3l-.3 .2M57.3 127.3h.1M58.2 127.3h.1M59.1 127.3h.1M60 127.3h.1M60.9 127.3h.1M61.9 127.3h.1M62.8 127.3h.1M63.7 127.3h.1M64.6 127.3h.1M65.5 127.3h.1"/>
<path d="M66.4 127.3h.1M67.4 127.3h.1M68.3 127.3h.1M69.2 127.3h.1M70.1 127.3h.1M71 127.3h.1M71.9 127.3h.1M72.9 127.3h.1M73.8 127.3h.1M74.7 127.3h.1M75.6 127.3h.1M76.5 127.3h.1"/>
<path d="M77.4 127.3h.1M78.3 127.3h.1M79.2 127.3h.2M80.2 127.3h.1M81.1 127.3h.1M82 127.3h.1M82.9 127.3h.1M83.8 127.3h.1M84.8 127.3h.1M85.7 127.3h.1M86.6 127.3h.1M87.5 127.3h.1"/>
<path d="M88.4 127.3h.1M89.3 127.3h.1M90.2 127.3h.1M91.2 127.3h.1M92.1 127.3h.1M93 127.3h.1M93.9 127.3h.1M94.8 127.3h.1M95.7 127.3h.1M96.6 127.3h.2M97.6 127.3h.1M98.5 127.3h.1"/>
<path d="M99.4 127.3h.1M100.3 127.3h.1M101.2 127.3h.1M102.2 127.3h.1M103.1 127.3h.1M103.8 133.2l1.1 1.1M104 127.3h.1M104.9 127.3h.1M105.8 127.3h.1M106.2 134.3v10.5M106.7 127.3h.1M107.6 127.3h.1"/>
<path d="M108.6 127.3h.1M109.5 127.3h.1M110.4 127.3h.1M111.3 127.3h.1M112.2 127.3h.1M113.1 127.3h.1M114 127.3h.2M115 127.3h.1M115.9 127.3h.1M116.8 127.3h.1M117.7 127.3h.1M118.6 127.3h.1"/>
<path d="M119.5 127.3h.2M120.5 127.3h.1M121.4 127.3h.1M122.3 127.3h.1M123.2 127.3h.1M124.1 127.3h.1M125 127.3h.1M125.9 127.3h.1M126.9 127.3h.1M127.8 127.3h.1M128.7 127.3h.1M129.6 127.3h.1"/>
<path d="M130.5 127.3h.1M131.4 127.3h.2M132.4 127.3h.1M133.3 127.3h.1M134.2 127.3h.1M135.1 127.3h.1M136 127.3h.1M136.9 127.3h.1M137.9 127.3h.1M138.8 127.3h.1M139.7 127.3h.1M140.6 127.3h.1"/>
<path d="M141.5 127.3h.1M142.4 127.3h.1M143.3 127.3h.1M144.3 127.3h.1M145.2 127.3h.1M146.1 127.3h.1M147 127.3h.1M147.9 127.3h.1M148.8 127.3h.1M149.8 127.3h.1M150.7 127.3h.1M151.6 127.3h.1"/>
<path d="M152.5 127.3h.1M153.4 127.3h.1M154.3 127.3l.1 .1M154.4 128.2v.1M154.4 129.2v.1M154.4 130.1v.1M154.4 131v.1M154.4 131.9v.1M154.4 132.8v.2M154.4 133.8v.1M154.4 134.7v.1M154.4 135.6v.1"/>
<path d="M154.4 136.5v.2M154.4 137.5v.1M154.4 138.4v.1M154.4 139.3v.1M55.4 140.3v.1M55.4 141.2v.1M55.4 142.1v.1M55.4 143v.2M55.4 144v.1M55.4 144.9v.1M55.4 145.8v.1M55.4 146.7v.1"/>
<path d="M55.4 147.6v.2M55.4 148.6v.1M55.4 149.5v.1M55.4 150.4v.1M55.4 151.3v.1M55.4 152.3v.1M55.4 153.2v.1M55.4 154.1v.1M55.4 155v.1M55.4 156v.1M55.4 156.9v.1M55.4 157.8v.1"/>
<path d="M55.4 158.7v.1M55.4 159.6v.1M154.4 140.2v.2M154.4 141.2v.1M154.4 142.1v.1M154.4 143v.1M154.4 143.9v.1M154.4 144.9v.1M154.4 145.8v.1M154.4 146.7v.1M154.4 147.6v.1M154.4 148.5v.2"/>
<path d="M154.4 149.5v.1M154.4 150.4v.1M154.4 151.3v.1M154.4 152.3v.1M154.4 153.2v.1M154.4 154.1v.1M154.4 155v.1M154.4 155.9v.2M154.4 156.9v.1M154.4 157.8v.1M154.4 158.7v.1M154.4 159.6v.1"/>
<path d="M55.4 160.6v.1M55.4 161.5v.1M55.4 162.4v.1M55.4 163.3v.1M55.4 164.3v.1M55.4 165.2v.1M55.4 166.1v.1M55.4 167v.1M55.4 168v.1M55.4 168.9v.1M55.4 169.8v.1M55.4 170.7v.1"/>
<path d="M55.4 171.6v.1M55.4 172.6l.1 .1M56.3 172.7h.1M57.3 172.7h.1M58.2 172.7h.1M59.1 172.7h.1M60 172.7h.1M60.9 172.7h.1M61.8 172.7h.1M62.7 172.7h.1M63.6 172.7h.2M64.6 172.7h.1"/>
<path d="M65.5 172.7h.1M66.4 172.7h.1M67.3 172.7h.1M68.2 172.7h.1M69.2 172.7h.1M70.1 172.7h.1M71 172.7h.1M71.9 172.7h.1M72.8 172.7h.1M73.7 172.7h.1M74.7 172.7h.1M75.6 172.7h.1"/>
<path d="M76.5 172.7h.1M77.4 172.7h.1M78.3 172.7h.1M79.2 172.7h.1M80.1 172.7h.1M81.1 172.7h.1M82 172.7h.1M82.9 172.7h.1M83.8 172.7h.1M84.7 172.7h.1M85.6 172.7h.1M86.6 172.7h.1"/>
<path d="M87.5 172.7h.1M88.4 172.7h.1M89.3 172.7h.1M90.2 172.7h.1M91.1 172.7h.1M92.1 172.7h.1M93 172.7h.1M93.9 172.7h.1M94.8 172.7h.1M95.7 172.7h.1M96.6 172.7h.1M97.6 172.7h.1"/>
<path d="M98.5 172.7h.1M99.4 172.7h.1M100.3 172.7h.1M101.2 172.7h.1M102.1 172.7h.1M103 172.7h.1M103.9 172.7h.2M104.9 172.7h.1M105.8 172.7h.1M106.7 172.7h.1M107.6 172.7h.1M108.5 172.7h.1"/>
<path d="M109.5 172.7h.1M110.4 172.7h.1M111.3 172.7h.1M112.2 172.7h.1M113.1 172.7h.1M114 172.7h.1M115 172.7h.1M115.9 172.7h.1M116.8 172.7h.1M117.7 172.7h.1M118.6 172.7h.1M119.5 172.7h.1"/>
<path d="M120.4 172.7h.1M121.4 172.7h.1M122.3 172.7h.1M123.2 172.7h.1M124.1 172.7h.1M125 172.7h.1M125.9 172.7h.1M126.9 172.7h.1M127.8 172.7h.1M128.7 172.7h.1M129.6 172.7h.1M130.5 172.7h.1"/>
<path d="M131.4 172.7h.1M132.4 172.7h.1M133.3 172.7h.1M134.2 172.7h.1M135.1 172.7h.1M136 172.7h.1M136.9 172.7h.1M137.8 172.7h.1M138.8 172.7h.1M139.7 172.7h.1M140.6 172.7h.1M141.5 172.7h.1"/>
<path d="M142.4 172.7h.1M143.3 172.7h.1M144.3 172.7h.1M145.2 172.7h.1M146.1 172.7h.1M147 172.7h.1M147.9 172.7h.1M148.8 172.7h.1M149.8 172.7h.1M150.7 172.7h.1M151.6 172.7h.1M152.5 172.7h.1"/>
<path d="M153.4 172.7h.1M154.4 160.5v.2M154.4 161.5v.1M154.4 162.4v.1M154.4 163.3v.1M154.4 164.3v.1M154.4 165.2v.1M154.4 166.1v.1M154.4 167v.1M154.4 168v.1M154.4 168.9v.1M154.4 169.8v.1"/>
<path d="M154.4 170.7v.1M154.4 171.6v.1M154.4 172.6l-.1 .1"/>
</g>
<g fill="none" stroke="#800000" stroke-width=".83">
<path d="M141.7 137.1l3.9 3.8v2.8M152.5 135.9h-7l-1.2-1.3h-4.5l-.9 1v4.4l-2.9 2.9M63.7 156.2h10.4M68.7 141.6l3.2 3.2v11.4l1.3 1.3h.9M70.7 156.2l.9 .9M71.6 159l1 1h1.5M71.6 156.2v4.4l.6 .6h4.2l1.2 1.3v3.8M71.6 157.5l1.3 1.2h1.2M76.4 141.6l4.4 4.4h1M85.9 155.6l-.7 .6h-1.5M85.9 156.8l-.7 .7h-1.5M85.9 158.1l-.7 .6h-1.5"/>
<path d="M89.7 152.4v2.8M95.4 152.4h-7.9l-1.6 1.6v5.3l-.7 .7h-1.5M103 160h-.3l7.3 7.3h3.1M103 154.9h1.9l5.1 5.1h17.1l2 1.9v1.3l1.9 1.9h5.2l2.3 2.2M103 157.5h.7l7.6 7.6h12.2l2.3 2.2M103 149.8h3.2M112.9 153.6h11.1M116.4 141.9h.5M116.4 141.9l-2.8 2.8v3.2M116.4 141.9v2.5l4.1 4.2h2.2M123 140.9l1.7 2h2.2M128.6 142.9v6.1l-1.6 1.6"/>
<path d="M130.3 142.9v9.1M132 142.9v2.3l3.4 3.4v2.5l-2.5 2.5h-1.3M133.7 142.9h2.3M136 142.9v2.3l9.5 9.5v2.1l-.6 .7h-33.6l-5.1-5.1h-5.7l-5.1-5.1h-1.3l-3.1 3.2h-10.2l-1.9 1.9v8.2l3.2 3.2h4.4M152.5 140.9h-4.1l-6.7 6.7v-.6M74.1 166.3h12l.7 .7h.3M74.1 165.1h-2.2l-.6 .6v2.5l.6 .7h17.1l2.6-2.6h2.5l1.3 1.3M74.1 163.8h-2.8l-1.3 1.3v3.8l1.3 1.2h24.7l1.3-1.2v-2.9l-.9-.9h-1M74.1 162.5h-4.1l-1.9 1.9h-2.8l-1.6-1.6M85.9 166.3l-1.3 1.3h-.9M86.5 163.8l.6 .6M92.5 160.6h-2.8l-3.2 3.2"/>
<path d="M92.5 168.2l1.9 1.9"/>
</g>
<g fill="none" stroke="#800000" stroke-width=".32">
<path d="M71.3 132.1l6.7 6.7h3.8M81.8 138.8l3.4-3.4h2.1l.5 .5v3.4M81.8 138.8v4.1M84.3 140l.3 .3h2.5M89.7 139.3v1.6M90.4 139.3v1l-1.3 1.3h-2M95.4 139.7l-1.9 1.9h-1.9l-2.6 2.5v1M95.4 137.1l1.6 1.6v3.8l-1 1h-4.4l-.6 .6v2.2l-1.3 1.3M103.8 133.2h-10l-4.8 4.8v2.3l-.3 .3h-1.2l-.4-.3v-1M106.2 134.3l-1.9-1.9h-11.1l-4.8 4.8v2.1M83.3 150.4l.1 .1M84.3 142.9h1.9l.9 .9v6.7"/>
<path d="M88.4 141.6v4.4h1.9l.1-.9M95.4 142.2h-3.7l-2 2v.9M95.4 144.8l-4.8 4.7h-2.8v-4.4"/>
</g>
<path d="M104.9 134.3v11.4M106.2 144.8l5.9 5.8h.1" fill="none" stroke="#800000" stroke-width=".51"/>
<path d="M104.9 145.7l8 7.9M112.2 150.6h14.8" fill="none" stroke="#800000" stroke-width=".61"/>
<circle cx="121.8" cy="145.8" r=".7" fill="#008000" stroke="#008000" stroke-width=".18"/>
<circle cx="121.8" cy="145.8" r=".44" fill="#fff" stroke="#000" stroke-width=".18"/>
<path d="M121.1 143h1.3v1.4h-1.3z" fill="#008000" stroke="#008000" stroke-width=".18"/>
<circle cx="121.8" cy="143.7" r=".44" fill="#fff" stroke="#000" stroke-width=".18"/>
<path d="M112.7 147h1.7v1.8h-1.7z" fill="#008000" stroke="#008000" stroke-width=".18"/>
<circle cx="113.6" cy="147.9" r=".44" fill="#fff" stroke="#000" stroke-width=".18"/>
<circle cx="116.6" cy="147.9" r=".89" fill="#008000" stroke="#008000" stroke-width=".18"/>
<circle cx="116.6" cy="147.9" r=".44" fill="#fff" stroke="#000" stroke-width=".18"/>
<circle cx="141.7" cy="142.6" r=".97" fill="#008000" stroke="#008000" stroke-width=".18"/>
<circle cx="141.7" cy="142.6" r=".44" fill="#fff" stroke="#000" stroke-width=".18"/>
<path d="M140.8 146.6h1.9v1.9h-1.9z" fill="#008000" stroke="#008000" stroke-width=".18"/>
<circle cx="141.7" cy="147.6" r=".44" fill="#fff" stroke="#000" stroke-width=".18"/>
<circle cx="141.7" cy="132.1" r=".97" fill="#008000" stroke="#008000" stroke-width=".18"/>
<circle cx="141.7" cy="132.1" r=".44" fill="#fff" stroke="#000" stroke-width=".18"/>
<path d="M140.8 136.1h1.9v2h-1.9z" fill="#008000" stroke="#008000" stroke-width=".18"/>
<circle cx="141.7" cy="137.1" r=".44" fill="#fff" stroke="#000" stroke-width=".18"/>
<circle cx="124" cy="153.6" r=".85" fill="#008000" stroke="#008000" stroke-width=".18"/>
<circle cx="124" cy="153.6" r=".55" fill="#fff" stroke="#000" stroke-width=".18"/>
<circle cx="131.6" cy="153.6" r=".85" fill="#008000" stroke="#008000" stroke-width=".18"/>
<circle cx="131.6" cy="153.6" r=".55" fill="#fff" stroke="#000" stroke-width=".18"/>
<path d="M134.7 148.6h1.4" fill="none" stroke="#008000" stroke-width="1.3"/>
<circle cx="135.4" cy="148.6" r=".4" fill="#fff" stroke="#000" stroke-width=".18"/>
<path d="M122 148.6h1.4" fill="none" stroke="#008000" stroke-width="1.3"/>
<circle cx="122.7" cy="148.6" r=".4" fill="#fff" stroke="#000" stroke-width=".18"/>
<circle cx="123" cy="133.3" r=".93" fill="#008000" stroke="#008000" stroke-width=".18"/>
<circle cx="123" cy="133.3" r=".44" fill="#fff" stroke="#000" stroke-width=".18"/>
<circle cx="123" cy="140.9" r=".93" fill="#008000" stroke="#008000" stroke-width=".18"/>
<circle cx="123" cy="140.9" r=".44" fill="#fff" stroke="#000" stroke-width=".18"/>
<circle cx="116.4" cy="141.9" r="2.16" fill="#008000" stroke="#008000" stroke-width=".18"/>
<circle cx="116.4" cy="141.9" r="1.5" fill="#fff" stroke="#000" stroke-width=".18"/>
<circle cx="116.4" cy="136" r="2.16" fill="#008000" stroke="#008000" stroke-width=".18"/>
<circle cx="116.4" cy="136" r="1.5" fill="#fff" stroke="#000" stroke-width=".18"/>
<circle cx="111.7" cy="139" r="2.16" fill="#008000" stroke="#008000" stroke-width=".18"/>
<circle cx="111.7" cy="139" r="1.5" fill="#fff" stroke="#000" stroke-width=".18"/>
<circle cx="152.5" cy="143.5" r=".93" fill="#008000" stroke="#008000" stroke-width=".18"/>
<circle cx="152.5" cy="143.5" r=".51" fill="#fff" stroke="#000" stroke-width=".18"/>
<circle cx="152.5" cy="140.9" r=".93" fill="#008000" stroke="#008000" stroke-width=".18"/>
<circle cx="152.5" cy="140.9" r=".51" fill="#fff" stroke="#000" stroke-width=".18"/>
<circle cx="152.5" cy="138.4" r=".93" fill="#008000" stroke="#008000" stroke-width=".18"/>
<circle cx="152.5" cy="138.4" r=".51" fill="#fff" stroke="#000" stroke-width=".18"/>
<circle cx="152.5" cy="135.9" r=".93" fill="#008000" stroke="#008000" stroke-width=".18"/>
<circle cx="152.5" cy="135.9" r=".51" fill="#fff" stroke="#000" stroke-width=".18"/>
<circle cx="57.3" cy="143.5" r=".93" fill="#008000" stroke="#008000" stroke-width=".18"/>
<circle cx="57.3" cy="143.5" r=".51" fill="#fff" stroke="#000" stroke-width=".18"/>
<circle cx="57.3" cy="140.9" r=".93" fill="#008000" stroke="#008000" stroke-width=".18"/>
<circle cx="57.3" cy="140.9" r=".51" fill="#fff" stroke="#000" stroke-width=".18"/>
<circle cx="57.3" cy="138.4" r=".93" fill="#008000" stroke="#008000" stroke-width=".18"/>
<circle cx="57.3" cy="138.4" r=".51" fill="#fff" stroke="#000" stroke-width=".18"/>
<circle cx="57.3" cy="135.9" r=".93" fill="#008000" stroke="#008000" stroke-width=".18"/>
<circle cx="57.3" cy="135.9" r=".51" fill="#fff" stroke="#000" stroke-width=".18"/>
<circle cx="86.1" cy="132.1" r=".7" fill="#008000" stroke="#008000" stroke-width=".18"/>
<circle cx="86.1" cy="132.1" r=".4" fill="#fff" stroke="#000" stroke-width=".18"/>
<circle cx="82.5" cy="132.1" r=".7" fill="#008000" stroke="#008000" stroke-width=".18"/>
<circle cx="82.5" cy="132.1" r=".4" fill="#fff" stroke="#000" stroke-width=".18"/>
<circle cx="71.3" cy="132.1" r=".93" fill="#008000" stroke="#008000" stroke-width=".18"/>
<circle cx="71.3" cy="132.1" r=".44" fill="#fff" stroke="#000" stroke-width=".18"/>
<circle cx="78.9" cy="132.1" r=".93" fill="#008000" stroke="#008000" stroke-width=".18"/>
<circle cx="78.9" cy="132.1" r=".44" fill="#fff" stroke="#000" stroke-width=".18"/>
<circle cx="125.8" cy="162.8" r=".93" fill="#008000" stroke="#008000" stroke-width=".18"/>
<circle cx="125.8" cy="162.8" r=".51" fill="#fff" stroke="#000" stroke-width=".18"/>
<circle cx="132.3" cy="162.8" r=".93" fill="#008000" stroke="#008000" stroke-width=".18"/>
<circle cx="132.3" cy="162.8" r=".51" fill="#fff" stroke="#000" stroke-width=".18"/>
<circle cx="125.8" cy="167.3" r=".93" fill="#008000" stroke="#008000" stroke-width=".18"/>
<circle cx="125.8" cy="167.3" r=".51" fill="#fff" stroke="#000" stroke-width=".18"/>
<circle cx="132.3" cy="167.3" r=".93" fill="#008000" stroke="#008000" stroke-width=".18"/>
<circle cx="132.3" cy="167.3" r=".51" fill="#fff" stroke="#000" stroke-width=".18"/>
<path d="M140.5 154.2v1.5" fill="none" stroke="#008000" stroke-width="1.5"/>
<circle cx="140.5" cy="154.9" r=".51" fill="#fff" stroke="#000" stroke-width=".18"/>
<path d="M143 154.2v1.5" fill="none" stroke="#008000" stroke-width="1.5"/>
<circle cx="143" cy="154.9" r=".51" fill="#fff" stroke="#000" stroke-width=".18"/>
<path d="M145.5 154.2v1.5" fill="none" stroke="#008000" stroke-width="1.5"/>
<circle cx="145.5" cy="154.9" r=".51" fill="#fff" stroke="#000" stroke-width=".18"/>
<circle cx="138.5" cy="162.8" r=".93" fill="#008000" stroke="#008000" stroke-width=".18"/>
<circle cx="138.5" cy="162.8" r=".51" fill="#fff" stroke="#000" stroke-width=".18"/>
<circle cx="145" cy="162.8" r=".93" fill="#008000" stroke="#008000" stroke-width=".18"/>
<circle cx="145" cy="162.8" r=".51" fill="#fff" stroke="#000" stroke-width=".18"/>
<circle cx="138.5" cy="167.3" r=".93" fill="#008000" stroke="#008000" stroke-width=".18"/>
<circle cx="138.5" cy="167.3" r=".51" fill="#fff" stroke="#000" stroke-width=".18"/>
<circle cx="145" cy="167.3" r=".93" fill="#008000" stroke="#008000" stroke-width=".18"/>
<circle cx="145" cy="167.3" r=".51" fill="#fff" stroke="#000" stroke-width=".18"/>
<circle cx="113.1" cy="162.8" r=".93" fill="#008000" stroke="#008000" stroke-width=".18"/>
<circle cx="113.1" cy="162.8" r=".51" fill="#fff" stroke="#000" stroke-width=".18"/>
<circle cx="119.6" cy="162.8" r=".93" fill="#008000" stroke="#008000" stroke-width=".18"/>
<circle cx="119.6" cy="162.8" r=".51" fill="#fff" stroke="#000" stroke-width=".18"/>
<circle cx="113.1" cy="167.3" r=".93" fill="#008000" stroke="#008000" stroke-width=".18"/>
<circle cx="113.1" cy="167.3" r=".51" fill="#fff" stroke="#000" stroke-width=".18"/>
<circle cx="119.6" cy="167.3" r=".93" fill="#008000" stroke="#008000" stroke-width=".18"/>
<circle cx="119.6" cy="167.3" r=".51" fill="#fff" stroke="#000" stroke-width=".18"/>
<circle cx="68.7" cy="141.6" r="1.17" fill="#008000" stroke="#008000" stroke-width=".18"/>
<circle cx="68.7" cy="141.6" r=".51" fill="#fff" stroke="#000" stroke-width=".18"/>
<circle cx="76.4" cy="141.6" r="1.17" fill="#008000" stroke="#008000" stroke-width=".18"/>
<circle cx="76.4" cy="141.6" r=".51" fill="#fff" stroke="#000" stroke-width=".18"/>
<circle cx="81.8" cy="146" r=".93" fill="#008000" stroke="#008000" stroke-width=".18"/>
<circle cx="81.8" cy="146" r=".44" fill="#fff" stroke="#000" stroke-width=".18"/>
<circle cx="81.8" cy="153.6" r=".93" fill="#008000" stroke="#008000" stroke-width=".18"/>
<circle cx="81.8" cy="153.6" r=".44" fill="#fff" stroke="#000" stroke-width=".18"/>
<path d="M102.2 166.8h1.7v1.6h-1.7z" fill="#008000" stroke="#008000" stroke-width=".18"/>
<circle cx="103" cy="167.6" r=".55" fill="#fff" stroke="#000" stroke-width=".18"/>
<circle cx="103" cy="165.1" r=".85" fill="#008000" stroke="#008000" stroke-width=".18"/>
<circle cx="103" cy="165.1" r=".55" fill="#fff" stroke="#000" stroke-width=".18"/>
<circle cx="103" cy="162.5" r=".85" fill="#008000" stroke="#008000" stroke-width=".18"/>
<circle cx="103" cy="162.5" r=".55" fill="#fff" stroke="#000" stroke-width=".18"/>
<circle cx="103" cy="160" r=".85" fill="#008000" stroke="#008000" stroke-width=".18"/>
<circle cx="103" cy="160" r=".55" fill="#fff" stroke="#000" stroke-width=".18"/>
<circle cx="103" cy="157.5" r=".85" fill="#008000" stroke="#008000" stroke-width=".18"/>
<circle cx="103" cy="157.5" r=".55" fill="#fff" stroke="#000" stroke-width=".18"/>
<circle cx="103" cy="154.9" r=".85" fill="#008000" stroke="#008000" stroke-width=".18"/>
<circle cx="103" cy="154.9" r=".55" fill="#fff" stroke="#000" stroke-width=".18"/>
<circle cx="103" cy="152.4" r=".85" fill="#008000" stroke="#008000" stroke-width=".18"/>
<circle cx="103" cy="152.4" r=".55" fill="#fff" stroke="#000" stroke-width=".18"/>
<circle cx="103" cy="149.8" r=".85" fill="#008000" stroke="#008000" stroke-width=".18"/>
<circle cx="103" cy="149.8" r=".55" fill="#fff" stroke="#000" stroke-width=".18"/>
<circle cx="103" cy="147.3" r=".85" fill="#008000" stroke="#008000" stroke-width=".18"/>
<circle cx="103" cy="147.3" r=".55" fill="#fff" stroke="#000" stroke-width=".18"/>
<circle cx="103" cy="144.8" r=".85" fill="#008000" stroke="#008000" stroke-width=".18"/>
<circle cx="103" cy="144.8" r=".55" fill="#fff" stroke="#000" stroke-width=".18"/>
<circle cx="103" cy="142.2" r=".85" fill="#008000" stroke="#008000" stroke-width=".18"/>
<circle cx="103" cy="142.2" r=".55" fill="#fff" stroke="#000" stroke-width=".18"/>
<circle cx="103" cy="139.7" r=".85" fill="#008000" stroke="#008000" stroke-width=".18"/>
<circle cx="103" cy="139.7" r=".55" fill="#fff" stroke="#000" stroke-width=".18"/>
<circle cx="103" cy="137.1" r=".85" fill="#008000" stroke="#008000" stroke-width=".18"/>
<circle cx="103" cy="137.1" r=".55" fill="#fff" stroke="#000" stroke-width=".18"/>
<circle cx="103" cy="134.6" r=".85" fill="#008000" stroke="#008000" stroke-width=".18"/>
<circle cx="103" cy="134.6" r=".55" fill="#fff" stroke="#000" stroke-width=".18"/>
<circle cx="95.4" cy="134.6" r=".85" fill="#008000" stroke="#008000" stroke-width=".18"/>
<circle cx="95.4" cy="134.6" r=".55" fill="#fff" stroke="#000" stroke-width=".18"/>
<circle cx="95.4" cy="137.1" r=".85" fill="#008000" stroke="#008000" stroke-width=".18"/>
<circle cx="95.4" cy="137.1" r=".55" fill="#fff" stroke="#000" stroke-width=".18"/>
<circle cx="95.4" cy="139.7" r=".85" fill="#008000" stroke="#008000" stroke-width=".18"/>
<circle cx="95.4" cy="139.7" r=".55" fill="#fff" stroke="#000" stroke-width=".18"/>
<circle cx="95.4" cy="142.2" r=".85" fill="#008000" stroke="#008000" stroke-width=".18"/>
<circle cx="95.4" cy="142.2" r=".55" fill="#fff" stroke="#000" stroke-width=".18"/>
<circle cx="95.4" cy="144.8" r=".85" fill="#008000" stroke="#008000" stroke-width=".18"/>
<circle cx="95.4" cy="144.8" r=".55" fill="#fff" stroke="#000" stroke-width=".18"/>
<circle cx="95.4" cy="147.3" r=".85" fill="#008000" stroke="#008000" stroke-width=".18"/>
<circle cx="95.4" cy="147.3" r=".55" fill="#fff" stroke="#000" stroke-width=".18"/>
<circle cx="95.4" cy="149.8" r=".85" fill="#008000" stroke="#008000" stroke-width=".18"/>
<circle cx="95.4" cy="149.8" r=".55" fill="#fff" stroke="#000" stroke-width=".18"/>
<circle cx="95.4" cy="152.4" r=".85" fill="#008000" stroke="#008000" stroke-width=".18"/>
<circle cx="95.4" cy="152.4" r=".55" fill="#fff" stroke="#000" stroke-width=".18"/>
<circle cx="95.4" cy="154.9" r=".85" fill="#008000" stroke="#008000" stroke-width=".18"/>
<circle cx="95.4" cy="154.9" r=".55" fill="#fff" stroke="#000" stroke-width=".18"/>
<circle cx="95.4" cy="157.5" r=".85" fill="#008000" stroke="#008000" stroke-width=".18"/>
<circle cx="95.4" cy="157.5" r=".55" fill="#fff" stroke="#000" stroke-width=".18"/>
<circle cx="95.4" cy="160" r=".85" fill="#008000" stroke="#008000" stroke-width=".18"/>
<circle cx="95.4" cy="160" r=".55" fill="#fff" stroke="#000" stroke-width=".18"/>
<circle cx="95.4" cy="162.5" r=".85" fill="#008000" stroke="#008000" stroke-width=".18"/>
<circle cx="95.4" cy="162.5" r=".55" fill="#fff" stroke="#000" stroke-width=".18"/>
<circle cx="95.4" cy="165.1" r=".85" fill="#008000" stroke="#008000" stroke-width=".18"/>
<circle cx="95.4" cy="165.1" r=".55" fill="#fff" stroke="#000" stroke-width=".18"/>
<circle cx="95.4" cy="167.6" r=".85" fill="#008000" stroke="#008000" stroke-width=".18"/>
<circle cx="95.4" cy="167.6" r=".55" fill="#fff" stroke="#000" stroke-width=".18"/>
<circle cx="63.7" cy="162.8" r="1.4" fill="#008000" stroke="#008000" stroke-width=".18"/>
<circle cx="63.7" cy="162.8" r=".93" fill="#fff" stroke="#000" stroke-width=".18"/>
<circle cx="63.7" cy="149.6" r="1.4" fill="#008000" stroke="#008000" stroke-width=".18"/>
<circle cx="63.7" cy="149.6" r=".93" fill="#fff" stroke="#000" stroke-width=".18"/>
<circle cx="106.8" cy="130.8" r=".93" fill="#008000" stroke="#008000" stroke-width=".18"/>
<circle cx="106.8" cy="130.8" r=".51" fill="#fff" stroke="#000" stroke-width=".18"/>
<circle cx="104.3" cy="130.8" r=".93" fill="#008000" stroke="#008000" stroke-width=".18"/>
<circle cx="104.3" cy="130.8" r=".51" fill="#fff" stroke="#000" stroke-width=".18"/>
<circle cx="101.7" cy="130.8" r=".93" fill="#008000" stroke="#008000" stroke-width=".18"/>
<circle cx="101.7" cy="130.8" r=".51" fill="#fff" stroke="#000" stroke-width=".18"/>
<circle cx="99.2" cy="130.8" r=".93" fill="#008000" stroke="#008000" stroke-width=".18"/>
<circle cx="99.2" cy="130.8" r=".51" fill="#fff" stroke="#000" stroke-width=".18"/>
<circle cx="96.7" cy="130.8" r=".93" fill="#008000" stroke="#008000" stroke-width=".18"/>
<circle cx="96.7" cy="130.8" r=".51" fill="#fff" stroke="#000" stroke-width=".18"/>
<circle cx="89.7" cy="155.2" r=".93" fill="#008000" stroke="#008000" stroke-width=".18"/>
<circle cx="89.7" cy="155.2" r=".44" fill="#fff" stroke="#000" stroke-width=".18"/>
<circle cx="89.7" cy="147.6" r=".93" fill="#008000" stroke="#008000" stroke-width=".18"/>
<circle cx="89.7" cy="147.6" r=".44" fill="#fff" stroke="#000" stroke-width=".18"/>
<circle cx="89.7" cy="168.2" r=".93" fill="#008000" stroke="#008000" stroke-width=".18"/>
<circle cx="89.7" cy="168.2" r=".44" fill="#fff" stroke="#000" stroke-width=".18"/>
<circle cx="89.7" cy="160.6" r=".93" fill="#008000" stroke="#008000" stroke-width=".18"/>
<circle cx="89.7" cy="160.6" r=".44" fill="#fff" stroke="#000" stroke-width=".18"/>
<circle cx="92.5" cy="160.6" r=".93" fill="#008000" stroke="#008000" stroke-width=".18"/>
<circle cx="92.5" cy="160.6" r=".44" fill="#fff" stroke="#000" stroke-width=".18"/>
<circle cx="92.5" cy="168.2" r=".93" fill="#008000" stroke="#008000" stroke-width=".18"/>
<circle cx="92.5" cy="168.2" r=".44" fill="#fff" stroke="#000" stroke-width=".18"/>
<circle cx="87.1" cy="164.4" r=".83" fill="#008000" stroke="#008000" stroke-width=".18"/>
<circle cx="87.1" cy="164.4" r=".44" fill="#fff" stroke="#000" stroke-width=".18"/>
<circle cx="87.1" cy="167" r=".83" fill="#008000" stroke="#008000" stroke-width=".18"/>
<circle cx="87.1" cy="167" r=".44" fill="#fff" stroke="#000" stroke-width=".18"/>
<circle cx="84.3" cy="142.9" r=".83" fill="#008000" stroke="#008000" stroke-width=".18"/>
<circle cx="84.3" cy="142.9" r=".44" fill="#fff" stroke="#000" stroke-width=".18"/>
<circle cx="81.8" cy="142.9" r=".83" fill="#008000" stroke="#008000" stroke-width=".18"/>
<circle cx="81.8" cy="142.9" r=".44" fill="#fff" stroke="#000" stroke-width=".18"/>
<circle cx="84.3" cy="140" r=".83" fill="#008000" stroke="#008000" stroke-width=".18"/>
<circle cx="84.3" cy="140" r=".44" fill="#fff" stroke="#000" stroke-width=".18"/>
<circle cx="81.8" cy="140" r=".83" fill="#008000" stroke="#008000" stroke-width=".18"/>
<circle cx="81.8" cy="140" r=".44" fill="#fff" stroke="#000" stroke-width=".18"/>
<circle cx="106.2" cy="149.8" r=".83" fill="#008000" stroke="#008000" stroke-width=".18"/>
<circle cx="106.2" cy="149.8" r=".44" fill="#fff" stroke="#000" stroke-width=".18"/>
<circle cx="106.2" cy="152.4" r=".83" fill="#008000" stroke="#008000" stroke-width=".18"/>
<circle cx="106.2" cy="152.4" r=".44" fill="#fff" stroke="#000" stroke-width=".18"/>
<g fill="#800000" stroke="#800000" stroke-width=".18">
<path d="M56 168a2.88 2.88 0 0 1 4.6 .2 2.88 2.88 0 0 1-1.5 4.4 2.88 2.88 0 0 1-3.7-2.8h2.5a.35 .35 0 0 1 .5-.4 .35 .35 0 0 1 .1 .6 .35 .35 0 0 1-.6-.1l-2.5-.1 .1-.6z" fill-rule="evenodd"/>
<path d="M56 128.4a2.89 2.89 0 0 1 4.7 .1 2.89 2.89 0 0 1-1.5 4.4 2.89 2.89 0 0 1-3.8-2.7h2.5a.35 .35 0 0 1 .5-.4 .35 .35 0 0 1 .1 .6 .35 .35 0 0 1-.6-.2h-2.5l.1-.7z" fill-rule="evenodd"/>
<path d="M149.3 128.4a2.88 2.88 0 0 1 4.7 .1 2.88 2.88 0 0 1-1.6 4.4 2.88 2.88 0 0 1-3.7-2.7h2.5a.35 .35 0 0 1 .6-.3 .35 .35 0 0 1 0 .6 .35 .35 0 0 1-.6-.3h-2.5l.3-1.3z" fill-rule="evenodd"/>
<path d="M149.8 167.6a2.89 2.89 0 0 1 4.4 .9 2.89 2.89 0 0 1-2 4.1 2.89 2.89 0 0 1-3.5-2.8h2.5a.35 .35 0 0 1 .6-.2 .35 .35 0 0 1 0 .6 .35 .35 0 0 1-.6-.3l-2.5-.1a2.87 2.87 0 0 1 1.1-2.2z" fill-rule="evenodd"/>
</g>
<g fill="none" stroke="#505050" stroke-width=".18">
<path d="M74.4 133.6h.3M74.4 133.2l.1-.1v.5M74.7 130.8h.1M74.8 130.8l.2-.2-.3-.1v.5M74.8 130.8l.2 .2M75 133.2a.2 .2 0 0 1 .2 .2 .2 .2 0 0 1-.2 .2zM75.2 133.2l-.2 .3M75.3 130.5l-.1 .4h.3M75.4 130.8v.2M75.5 133.1v.5M75.6 133.3l.2 .3M75.8 133.1l-.3 .3"/>
<path d="M76 139h.8M76.4 138.7v.7M82 138.5h.1a.2 .2 0 0 1 .2 .2 .2 .2 0 0 1-.3 .2zM82.2 138.6l-.2 .2M82.5 138.9h.1M82.8 138.6l.1-.1v.4M82.8 138.9h.2M82.8 129.9l.1 .4 .2 .2h2.2l.2 .1v.2l-.2 .1-1.8 .1v.2l.2 .1h1l.2 .2-.2 .2-.8 .1 .1 .2 .6 .1 .1 .3-.9 .1-.1 .3 1.3 .1 .1 .2-.2 .2h-1.5l-.1 .2 .2 .2h1.9l.3 .2 .1 .3M83.4 138.8v.1l.2-.1M83.4 138.6v.5M83.6 138.9h.1M83.6 138.6v.3"/>
<path d="M83.9 138.7h.2M84.1 138.5h-.2v.4M86.6 139.9h5v4.6h-5zM94.8 139.1h.7v1.2h-.7zM94.8 136.6h.7v1.1h-.7zM94.8 134h.7v1.2h-.7zM95.5 133.7h7.5v34.8h-7.5zM103 134h.6v1.2h-.6zM103 136.6h.6v1.1h-.6zM103 139.1h.6v1.2h-.6zM107.5 132.2v.5h-.2M107.8 132.4l.2-.1-.2 .4h.2"/>
<path d="M113.1 129.4h.2v-.2l-.2-.1v.5M113.6 129.2h.3v.4h-.3zM114.2 129.1l.1 .5 .1-.3 .1 .3 .1-.5M114.9 129.3h.1M115.1 129.1h-.2v.5h.2M115.4 129.4h.1M115.5 129.4l.1-.2-.2-.1v.5M115.5 129.4l.1 .2M115.9 129.7h.2M116.4 129.1v.4l-.1 .1M116.7 129.6l.2-.5 .1 .5M116.8 129.5h.2"/>
<path d="M117.1 130.2v.3l-.2 .1M117.4 130.6h.3M117.4 130.3l.1-.1v.4M117.5 129.1l-.2 .1v.4h.2M117.8 129.1v.5M117.9 129.3l.1 .3M118 129.1l-.2 .3M121.5 137h.4M121.5 136.7l.3 .3M121.7 137.4l.1-.1 .1 .3M121.7 137.4h-.2v.2M121.7 137.4v.1"/>
<path d="M121.9 136.7l-.3 .2M124.4 137.5l-.1-.2h-.2v.2h.5M124.6 137.3l-.2 .1M124.6 136.9h-.5l.1 .1M124.6 136.7v.3M136 133.4v.2h.5M136 134.5a.21 .21 0 0 1 .3-.1 .21 .21 0 0 1 .1 .3h-.3zM136.1 134.5l.3 .2M136.1 134.1h.5M136.2 133.4v.2M136.4 133.9v.2M136.5 135.6v.2l-.5-.2 .1 .2"/>
<path d="M136.5 135v.3l-.5-.3 .1 .3M136.5 133.9h-.4M147 135.8l.1 .2h.3l.1-.2M147 134.3h.5l-.1 .2h-.4M147 133.7v.3M147 133.9h.5M147.1 134.9h.3l.1 .1-.4 .1zM147.5 133.2v.3l-.5-.3 .1 .3M147.6 135.3v.3M55.4 144.5h.4l.1 .2M55.4 143.5a.22 .22 0 0 1 .3-.1 .22 .22 0 0 1 .1 .3h-.4zM55.5 143.4l.3 .3"/>
<path d="M55.9 144v.2M55.9 144.1h-.5l.1 .1M56.6 158.8l.1 .6 .8 .1 .3-.2v-.5h-.7v.2M57.8 157.6v.7M57.8 158h-1.2l.3 .3M58 156v.4M58 156.9l.3 1.1M58.4 154.1l-.3 .8M58.7 159l.2 .3M58.8 150.2a1.61 1.61 0 0 1 1.3-.4v-.2h7.1v.2l2.8 2.8h.3v7.1h-.2l-2.9 2.9v.1h-7.1v-.2a1.65 1.65 0 0 1-1.7-1.1 1.65 1.65 0 0 1 .5-1.9 6.9 6.9 0 0 0-.5-7.7 1.53 1.53 0 0 1 .4-1.6zM59.1 152.8l-.4 .5M59.2 159.7l.7 .8"/>
<path d="M60.2 151.6l-.8 .7M60.5 158.5h4.8a.8 .8 0 0 1 .8 .8 .8 .8 0 0 1-.8 .8h-4.8M60.5 152.2h4.6a.8 .8 0 0 1 .8 .8 .8 .8 0 0 1-.8 .8h-4.6M60.6 152.4v1.2M60.6 158.7v1.2M60.7 152.5v1M60.7 158.8v1M60.9 152.6v.8M60.9 158.9v.8M61 151.1l-.3 .1M62.9 149.5v-.7h1.5v.7M63.1 150.4l-1.1 .2"/>
<path d="M63.5 153.9a1.96 1.96 0 0 0 3 .6 1.96 1.96 0 0 0 0-3 1.96 1.96 0 0 0-3 .6 1.95 1.95 0 0 1 3.3-.4 1.95 1.95 0 0 1-.9 3.2M63.5 152.4v1.2M63.5 158.7v1.2M63.6 150.3h.4M63.7 152.5v1M63.7 158.8v1M63.9 152.6v.9M63.9 158.9v.8M65.1 150.5l.8 .2M65.9 157.4a1.96 1.96 0 0 1 .8 3.1 1.96 1.96 0 0 1-3.2-.4 1.96 1.96 0 0 0 3 .7 1.96 1.96 0 0 0 0-3.1 1.96 1.96 0 0 0-3 .7M66.7 151.1l.5 .3M67.7 151.8l.7 .8"/>
<path d="M68.7 153.1l.2 .3M68.9 159l-.3 .6M69.4 154.4l.2 1M69.5 157.5l-.2 .7M69.6 156v.4M71 156.9v.6M71 157.2h1.2M71.1 159.2h.3l.1 .2 .1-.3h.3l.2 .1 .1 .5h-1.2zM71.5 159.4v.3M71.9 158v.6M72.2 157.9l-1.2 .4 1.2 .4M75.2 155.6h7.4v12.6h-7.4z"/>
<path d="M80.2 149.8a.21 .21 0 0 1 .3-.1 .21 .21 0 0 1 .1 .2l-.3 .1zM80.2 149.2a.21 .21 0 0 1 .3-.1 .21 .21 0 0 1 .1 .3h-.3zM80.3 149.7l.3 .2M80.3 149.2l.3 .2M80.7 150.4h-.5l.1 .1M80.7 150.2v.3M82 141.4l.1-.1a.2 .2 0 0 1 .2 .3 .2 .2 0 0 1-.3 .1zM82.2 141.4l-.2 .3M82.5 141.8h.1M82.8 141.4l.1-.1v.5M82.8 141.8h.2M82.9 143.9l-.2 .1v.4h.2"/>
<path d="M82.9 141.1l-.2 .1v.3h.2M83.1 150.2v-.2h-.2l-.1 .2h.5M83.1 144h.3l-.3 .4h.3M83.1 141.1h.3v.2h-.2M83.2 141.3l.2 .2h-.3M83.3 149.4v.3l-.4-.2 .1 .2M83.3 150l-.2 .1M83.4 141.7v.1l.2-.1M83.4 141.5v.4M83.6 141.5v.3M83.9 141.5h.2M84.1 141.3h-.2v.5"/>
<path d="M86.8 140.2h4.5v4.1h-4.5zM88.3 151.2l.2-.2 .1 .3M88.3 151.2l-.1-.2-.1 .3M88.4 151.8v-.2h-.2l-.1 .2h.5M88.6 151.6l-.2 .1M90.8 151h.4M90.8 150.7l.3 .3M90.8 151.4a.22 .22 0 0 1 .2-.1 .22 .22 0 0 1 .2 .2h-.4zM90.9 151.3l.2 .3M91.2 151.8v.3l-.4-.2 .1 .2M91.2 150.7l-.2 .2M94.8 159.4h.7v1.1h-.7z"/>
<path d="M94.8 156.9h.7v1.1h-.7zM94.8 154.3h.7v1.2h-.7zM94.8 151.8h.7v1.1h-.7zM94.8 149.3h.7v1.1h-.7zM94.8 146.7h.7v1.1h-.7zM94.8 144.2h.7v1.1h-.7zM94.8 141.7h.7v1.1h-.7zM103 141.7h.6v1.1h-.6zM103 144.2h.6v1.1h-.6zM103 146.7h.6v1.1h-.6zM103 149.3h.6v1.1h-.6M103 151.8h.6v1.1h-.6"/>
<path d="M103 154.3h.6v1.2h-.6M103 156.9h.6v1.1h-.6M103 159.4h.6v1.1h-.6M104.6 150.1v.2h.5M104.7 152a.22 .22 0 0 1 .2-.1 .22 .22 0 0 1 .2 .2h-.4zM104.8 151.9l.2 .2M104.8 150.8h.5M104.9 150.1v.2M105 150.6h.1l-.1 .2M105.1 151.6h.1M105.1 150.5l-.3 .1M105.1 151.1v.3"/>
<path d="M105.1 151.2h-.5l.2 .2M107.3 151.3l.1 .2 .3-.1v-.1M107.5 150.8h.2M107.6 150.7v.3l-.3-.1M125.6 147.1l5.4 .1 .1-.2 1.3 .1 .2 .2v2.6l-.2 .2h-1.3l-.1-.1-5.4 .1-.1-.3zM125.7 152.7h4.2v1.9h-4.2zM125.8 147.4v2.3M127 147.4v2.3M127.1 153.6h2.2M127.8 153.6l1-.6v1.3zM127.8 153v1.3M131.1 147.4v2.3"/>
<path d="M132.4 147.4v2.3M136 143.9v.2h.5M136 145a.21 .21 0 0 1 .3-.1 .21 .21 0 0 1 .1 .2l-.3 .1zM136.1 144.9l.3 .3M136.1 144.6h.5M136.2 143.9v.2M136.4 144.4v.2M136.5 146v.3l-.5-.3 .1 .3M136.5 145.5v.2l-.5-.2 .1 .2M136.5 144.3l-.4 .1M137.9 153.5v2.9l.3 .3h9.6l.3-.3v-2.9M147 146.2l.1 .3h.3l.1-.3"/>
<path d="M147 144.7l.5 .1-.1 .2h-.4M147 144.2v.3M147 144.3h.5M147.1 145.3h.3l.1 .2h-.4zM147.5 143.7v.3M147.5 143.8h-.5l.1 .2M147.6 145.8v.2M150.6 144.5h.4l.1 .2M151.1 144.1l-.5-.1v.2M60.4 160.9l.5 .3M61.7 161.6l.8 .3M62.9 162.8v.7h1.5v-.7"/>
<path d="M63.6 162h.4M65.6 161.7l-1 .3M66.9 161.1l-.3 .2M68.2 160l-.8 .8M85.6 164.7v.2h.5M85.6 166.5a.22 .22 0 0 1 .3-.1 .22 .22 0 0 1 .1 .3h-.2zM85.7 166.5l.3 .2M85.8 165.4h.5M85.8 164.7v.2M86 165.2h.1l-.1 .2M86.1 166.2h.1M86.1 165.1l-.3 .1"/>
<path d="M86.1 165.7v.3M86.1 165.8h-.5l.1 .2M88.1 164v.3h.2l.2-.3 .1 .1v.2M88.2 165.8l.1 .3h.3l.1-.3M88.4 164.8v-.2h-.2l-.1 .2h.5M88.6 164.6l-.2 .1M88.7 165.3v.3M88.7 165.5h-.5l.1 .1M90.8 164h.7M90.8 163.7l.3 .3M90.8 164.4a.22 .22 0 0 1 .2-.1 .22 .22 0 0 1 .2 .2l-.3 .1zM90.9 164.3l.2 .2"/>
<path d="M91 164.4a.22 .22 0 0 1 .3-.1 .22 .22 0 0 1 .1 .2l-.3 .1zM91 163.7l.3 .3M91.1 164.3l.3 .2M91.2 164.9v.2l-.4-.2 .1 .2M91.2 163.7l-.2 .2M91.5 164.9v.2l-.5-.2 .1 .2M91.5 163.7l-.3 .2M93.6 164.1l.2 .2M93.9 164.8v-.2h-.2l-.1 .2h.5M94 164l-.2 .3M94 164h.1M94 164l.1 .3h-.3"/>
<path d="M94.1 164.6l-.2 .1M94.8 167h.7v1.2h-.7zM94.8 164.5h.7v1.1h-.7zM94.8 162h.7v1.1h-.7zM98.9 168.5l.2-.3 .3 .1 .1 .2M103 167h.6v1.2h-.6M103 162h.6v1.1h-.6M103 164.5h.6v1.1h-.6M116.2 161.3l-.2-.1v.2l.2 .2h-.2M116.5 161.2l.3 .1-.3 .1M116.5 168.5l-.3 .1 .3 .1M116.6 161.4l.1 .2-.2 .1"/>
<path d="M128.9 161.3h-.2l.2 .3h-.2M128.9 168.5l.2 .3 .1-.3M129.2 161.3l.1-.1v.5M129.2 161.7h.3M141.6 161.3h-.2l.2 .3h-.2M141.6 168.5l.3 .1-.3 .1M141.9 161.3h.2l-.2 .4h.2"/>
<circle cx="58.3" cy="130.1" r="2.86"/>
<circle cx="151.6" cy="130.1" r="2.86"/>
<circle cx="72.6" cy="141.6" r="6.1"/>
<circle cx="72.6" cy="141.6" r="1.27"/>
<circle cx="115.1" cy="147.9" r="3.2"/>
<circle cx="121.8" cy="144.8" r="2.03"/>
<circle cx="58.3" cy="169.8" r="2.86"/>
<circle cx="151.6" cy="169.8" r="2.86"/>
</g>
<path d="M117.6 146.7v2.5M121.1 146.7h1.3" fill="none" stroke="#505050" stroke-width=".32"/>
<g fill="none" stroke="#505050" stroke-width=".21">
<path d="M56.7 134.6h1.3l.6 .6v1.3l-.6 .6 .6 .7v1.2l-.6 .7 .6 .6v1.3l-.6 .6 .6 .7v1.2l-.6 .7h-1.3l-.7-.7v-1.2l.7-.7-.7-.6v-1.3l.7-.6-.7-.7v-1.2l.7-.7-.7-.6v-1.3zM72.3 132.1h.3M72.6 131.3h5v1.5h-5zM77.6 132.1h.3M82.1 140h.4M82.5 139.4v1.2M83.5 140h.5M83.5 139.4v1.2M85.8 134.4h-3a2.69 2.69 0 0 1 0-4.6h3a2.7 2.7 0 0 1 0 4.6M95.4 130.2l.6-.7h1.3l.6 .7 .7-.7h1.2l.7 .7 .6-.7h1.3l.6 .7 .7-.7h1.2l.7 .7 .6-.7h1.3l.6 .7v1.2l-.6 .7h-1.3l-.6-.7-.7 .7h-1.2l-.7-.7-.6 .7h-1.3l-.6-.7-.7 .7h-1.2l-.7-.7-.6 .7h-1.3l-.6-.7zM111.8 136.5v-8.1h9v13.5h-2.1M111.8 131.3h9"/>
<path d="M122.3 134.6h1.5v5.1h-1.5zM123 134.3v.3M123 139.7v.2M125.2 130h10.2v10h-10.2zM125.2 129.5v.4h10.2v-.4M125.2 129.5l1.7-.5h6.8l1.7 .5M125.2 129.7h10.2M125.2 129.5h10.2M125.7 129.3h9.2M126.4 129.2h7.9M143.6 137.1h1.3M144.3 131.4v1.3"/>
<path d="M144.3 136.5v1.3M151.9 134.6h1.3l.6 .6v1.3l-.6 .6 .6 .7v1.2l-.6 .7 .6 .6v1.3l-.6 .6 .6 .7v1.2l-.6 .7h-1.3l-.6-.7v-1.2l.6-.7-.6-.6v-1.3l.6-.6-.6-.7v-1.2l.6-.7-.6-.6v-1.3zM81 147.3h1.5v5.1h-1.5zM81.8 147v.3M81.8 152.4v.2M82.1 142.9h.4M82.5 142.2v1.3M83.5 142.2v1.3M83.5 142.9h.5M88.9 148.9h1.5v5.1h-1.5zM89.7 148.6v.3M89.7 154v.2"/>
<path d="M105.6 150.6h1.2M105.6 151.6h1.2M106.2 150.1v.5M106.2 151.6v.5M111.8 141.2v.7h2.2M143.6 147.6h1.3M144.3 141.9v1.3M144.3 147v1.3M86.5 165.2h1.3M86.5 166.2h1.3M87.1 164.7v.5M87.1 166.2v.5"/>
<path d="M88.9 161.9h1.5v5.1h-1.5zM89.7 161.6v.3M89.7 167v.2M91.8 161.9h1.5v5.1h-1.5zM92.5 161.6v.3M92.5 167v.2M113.3 162.5l.5-.5h5.1l.5 .5v5.1l-.5 .5h-5.1l-.5-.5zM113.8 163.8v.7l.4 .9M113.8 165.6v.7M126.5 162h5.1l.5 .5v5.1l-.5 .5h-5.1l-.5-.5v-5.1zM126.5 163.8v.7l.4 .9M126.5 165.6v.7"/>
<path d="M139.2 162h5.1l.5 .5v5.1l-.5 .5h-5.1l-.5-.5v-5.1zM139.2 163.8v.7l.4 .9M139.2 165.6v.7"/>
<circle cx="141.7" cy="134.6" r="5"/>
<circle cx="141.7" cy="145.1" r="5"/>
<circle cx="116.4" cy="165.1" r="1.78"/>
<circle cx="129.1" cy="165.1" r="1.78"/>
<circle cx="141.7" cy="165.1" r="1.78"/>
</g>
<g fill="#505050" stroke="#505050" stroke-width=".18">
<path d="M126.1 152.7h.5v1.9h-.5z"/>
<path d="M129.9 153.2h.6v.9h-.6z"/>
<path d="M125.1 153.2h.6v.9h-.6z"/>
<path d="M123.5 148.3h2v.6h-2z"/>
<path d="M132.6 148.3h1.9v.6h-1.9z"/>
<path d="M126.4 139.9h1v1.7h-1z"/>
<path d="M128.1 139.9h1v1.7h-1z"/>
<path d="M129.8 139.9h1v1.7h-1z"/>
<path d="M131.5 139.9h1v1.7h-1z"/>
<path d="M133.2 139.9h1v1.7h-1z"/>
<path d="M137.7 152.4h1.9v1.2h-1.9z"/>
<path d="M139.6 152.4h1.8v.7h-1.8z"/>
<path d="M141.4 152.4h.7v1.2h-.7z"/>
<path d="M142.1 152.4h1.8v.7h-1.8z"/>
<path d="M143.9 152.4h.8v1.2h-.8z"/>
<path d="M144.7 152.4h1.7v.7h-1.7z"/>
<path d="M146.4 152.4h1.9v1.2h-1.9z"/>
<path d="M67.1 156h2.2v.4h-2.2z"/>
<path d="M67.9 155.1h.4v2.2h-.4z"/>
<path d="M126.4 141.6h1v2.1h-1z"/>
<path d="M128.1 141.6h1v2.1h-1z"/>
<path d="M129.8 141.6h1v2.1h-1z"/>
<path d="M131.5 141.6h1v2.1h-1z"/>
<path d="M133.2 141.6h1v2.1h-1z"/>
<path d="M152.3 135.6h.5v.5h-.5z"/>
<path d="M152.3 138.2h.5v.5h-.5z"/>
<path d="M152.3 140.7h.5v.5h-.5z"/>
<path d="M152.3 143.2h.5v.5h-.5z"/>
<path d="M57.1 135.6h.5v.5h-.5z"/>
<path d="M57.1 138.2h.5v.5h-.5z"/>
<path d="M57.1 140.7h.5v.5h-.5z"/>
<path d="M57.1 143.2h.5v.5h-.5z"/>
<path d="M139.6 153.1h1.8v.5h-1.8z"/>
<path d="M142.1 153.1h1.8v.5h-1.8z"/>
<path d="M144.7 153.1h1.7v.5h-1.7z"/>
<path d="M73.8 156h1.3v.4h-1.3z"/>
<path d="M73.8 157.2h1.3v.5h-1.3z"/>
<path d="M73.8 158.5h1.3v.4h-1.3z"/>
<path d="M73.8 159.8h1.3v.4h-1.3z"/>
<path d="M73.8 161h1.3v.5h-1.3z"/>
<path d="M73.8 162.3h1.3v.4h-1.3z"/>
<path d="M73.8 163.6h1.3v.4h-1.3z"/>
<path d="M73.8 164.8h1.3v.5h-1.3z"/>
<path d="M73.8 166.1h1.3v.4h-1.3z"/>
<path d="M73.8 167.4h1.3v.4h-1.3z"/>
<path d="M82.7 156h1.3v.4h-1.3z"/>
<path d="M82.7 157.2h1.3v.5h-1.3z"/>
<path d="M82.7 158.5h1.3v.4h-1.3z"/>
<path d="M82.7 159.8h1.3v.4h-1.3z"/>
<path d="M82.7 161h1.3v.5h-1.3z"/>
<path d="M82.7 162.3h1.3v.4h-1.3z"/>
<path d="M82.7 163.6h1.3v.4h-1.3z"/>
<path d="M82.7 164.8h1.3v.5h-1.3z"/>
<path d="M82.7 166.1h1.3v.4h-1.3z"/>
<path d="M82.7 167.4h1.3v.4h-1.3z"/>
<path d="M87 144.5h.2v.9h-.2z"/>
<path d="M87.7 144.5h.2v.9h-.2z"/>
<path d="M88.3 144.5h.2v.9h-.2z"/>
<path d="M88.9 144.5h.3v.9h-.3z"/>
<path d="M89.6 144.5h.2v.9h-.2z"/>
<path d="M90.3 144.5h.2v.9h-.2z"/>
<path d="M90.9 144.5h.2v.9h-.2z"/>
<path d="M90.9 139.1h.2v.9h-.2z"/>
<path d="M90.3 139.1h.2v.9h-.2z"/>
<path d="M89.6 139.1h.2v.9h-.2z"/>
<path d="M88.9 139.1h.3v.9h-.3z"/>
<path d="M88.3 139.1h.2v.9h-.2z"/>
<path d="M87.7 139.1h.2v.9h-.2z"/>
<path d="M87 139.1h.2v.9h-.2z"/>
<path d="M96.4 130.5h.5v.5h-.5z"/>
<path d="M99 130.5h.5v.5h-.5z"/>
<path d="M101.5 130.5h.5v.5h-.5z"/>
<path d="M104 130.5h.5v.5h-.5z"/>
<path d="M106.6 130.5h.5v.5h-.5z"/>
</g>
<g fill="#505050" stroke="#505050" stroke-width=".18">
<path d="M75.7 138.5a.84 .84 0 0 1 1.4 .1 .84 .84 0 0 1-.5 1.2 .84 .84 0 0 1-1.1-.8h.2a.69 .69 0 0 1 .9-.6 .69 .69 0 0 1 .2 1.1 .69 .69 0 0 1-1.1-.2v-.3h-.2z" fill-rule="evenodd"/>
<path d="M81.2 166.8a.61 .61 0 0 1 1 .1 .61 .61 0 0 1-.3 .9 .61 .61 0 0 1-.8-.5h.1a.46 .46 0 0 1 .7-.4 .46 .46 0 0 1 .1 .8 .46 .46 0 0 1-.8-.3v-.1h-.1z" fill-rule="evenodd"/>
<path d="M87.1 143a.53 .53 0 0 1 .8 .2 .53 .53 0 0 1-.4 .8 .53 .53 0 0 1-.6-.6h.2a.38 .38 0 0 1 .5-.3 .38 .38 0 0 1 .1 .6 .38 .38 0 0 1-.6-.1v-.2h-.2z" fill-rule="evenodd"/>
<circle cx="138.4" cy="156.1" r=".25"/>
</g>
<path d="M124 153.6h1.3M130.3 153.6h1.3" fill="none" stroke="#505050" stroke-width=".87"/>
<path d="M122.7 148.6h1.1M134.3 148.6h1.1" fill="none" stroke="#505050" stroke-width=".61"/>
<g fill="none" stroke="#000" stroke-width=".18">
<path d="M74.1 132.1h2M75.1 131v2.1M82 140h2M83 139v2M83.3 132.1h2M84.3 131v2.1M94.4 134.6h2M95.4 133.6v2M105.8 130.8h2M106.8 129.8v2M115.3 128.3h2.1M116.4 127.3v2"/>
<path d="M122 137.1h2M123 136.1v2.1M129.3 137.1h2M130.3 136.1v2.1M140.7 134.6h2M141.7 133.6v2M56.3 143.5h2M57.3 142.5v2M62.7 156.2h2M63.7 155.2v2M71.5 141.6h2.1M72.6 140.6v2"/>
<path d="M80.8 149.8h2M81.8 148.8v2.1M82 142.9h2M83 141.8v2.1M88.2 142.2h1.7M88.7 151.4h2M89 141.4v1.7M89.7 150.4v2M105.2 151.1h2M106.2 150.1v2M114.1 147.9h2M115.1 146.9v2"/>
<path d="M120.7 144.8h2.1M121.8 143.7v2.1M126.8 153.6h2M127.8 152.6v2.1M128 148.6h2.1M129.1 147.6v2M140.7 145.1h2M141.7 144.1v2M142 152.4h2M143 151.4v2M151.5 143.5h2M152.5 142.5v2"/>
<path d="M77.9 161.9h2M78.9 160.9v2M86.1 165.7h2.1M87.1 164.7v2M88.7 164.4h2M89.7 163.4v2M91.5 164.4h2.1M92.5 163.4v2M115.3 165.1h2.1M116.4 164v2.1M128 165.1h2.1M129.1 164v2.1"/>
<path d="M140.7 165.1h2M141.7 164v2.1"/>
</g>
<g fill="none" stroke="#f90" stroke-width=".18">
<path d="M56.2 127.8a2.4 2.4 0 0 1 1.5-.5h94.4a2.26 2.26 0 0 1 2.3 2.2v40.9a2.29 2.29 0 0 1-2.3 2.3h-94.4a2.29 2.29 0 0 1-2.3-2.3v-40.8a2.31 2.31 0 0 1 .8-1.8z"/>
<circle cx="58.3" cy="169.8" r="1.5"/>
</g>
<circle cx="58.3" cy="169.8" r="1.5" fill="#fff" stroke="#000" stroke-width=".18"/>
<circle cx="58.3" cy="130.1" r="1.5" fill="none" stroke="#f90" stroke-width=".18"/>
<circle cx="58.3" cy="130.1" r="1.5" fill="#fff" stroke="#000" stroke-width=".18"/>
<circle cx="151.6" cy="130.1" r="1.5" fill="none" stroke="#f90" stroke-width=".18"/>
<circle cx="151.6" cy="130.1" r="1.5" fill="#fff" stroke="#000" stroke-width=".18"/>
<circle cx="151.6" cy="169.8" r="1.5" fill="none" stroke="#f90" stroke-width=".18"/>
<circle cx="151.6" cy="169.8" r="1.5" fill="#fff" stroke="#000" stroke-width=".18"/>
<g fill="none" stroke="#505050" stroke-width=".18">
<path d="M59.3 129.1l-2 2M152.6 129.1l-2 2M59.3 168.8l-2 2M152.6 168.8l-2 2"/>
<circle cx="58.3" cy="130.1" r=".99"/>
<circle cx="151.6" cy="130.1" r=".99"/>
<circle cx="58.3" cy="169.8" r=".99"/>
<circle cx="151.6" cy="169.8" r=".99"/>
</g>
<use href="#words"/>
</svg>
